FUNCTION_BLOCK "DIAGNOSTICA"
TITLE =Diagnostica
AUTHOR : D_T
VERSION : 0.1

BEGIN
NETWORK
TITLE =Mess.#001 - Emergenze non ripristinate

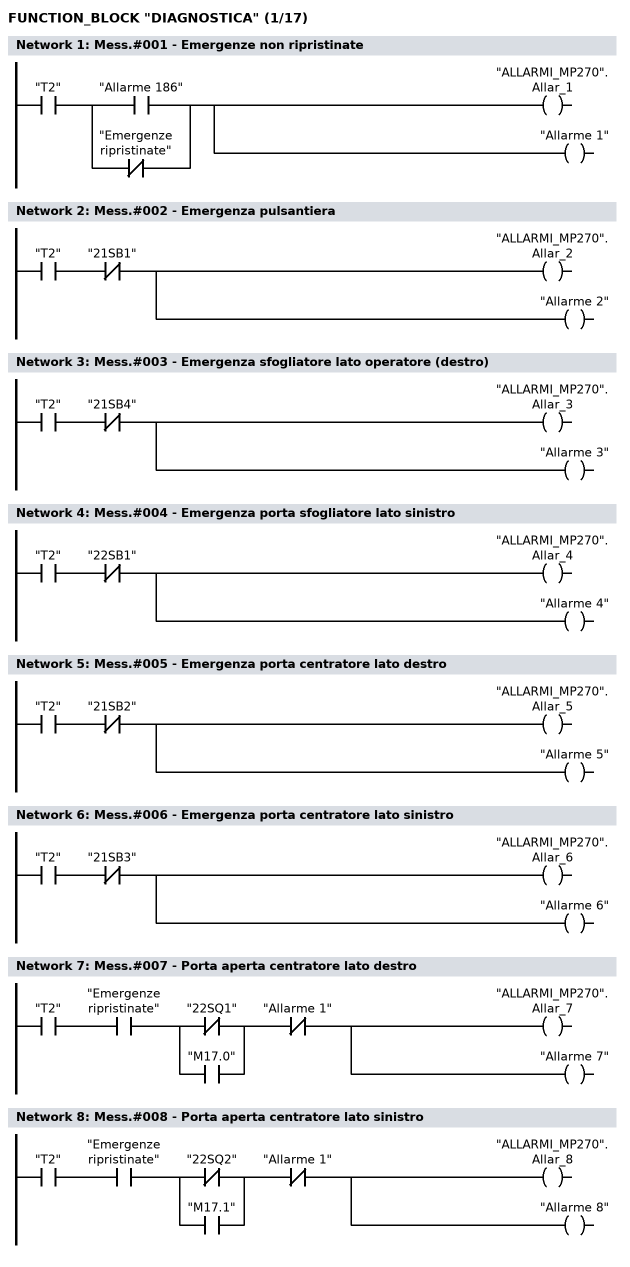
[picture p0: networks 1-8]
      U     "T2";
      U(    ;
      O     "Allarme 186";
      ON    "Emergenze ripristinate";
      )     ;
      =     "ALLARMI_MP270".Allar_1;
      =     "Allarme 1";
NETWORK
TITLE =Mess.#002 - Emergenza pulsantiera

      U     "T2";
      UN    "21SB1";
      =     "ALLARMI_MP270".Allar_2;
      =     "Allarme 2";
NETWORK
TITLE =Mess.#003 - Emergenza sfogliatore lato operatore (destro)

      U     "T2";
      UN    "21SB4";
      =     "ALLARMI_MP270".Allar_3;
      =     "Allarme 3";
NETWORK
TITLE =Mess.#004 - Emergenza porta sfogliatore lato sinistro

      U     "T2";
      UN    "22SB1";
      =     "ALLARMI_MP270".Allar_4;
      =     "Allarme 4";
NETWORK
TITLE =Mess.#005 - Emergenza porta centratore lato destro

      U     "T2";
      UN    "21SB2";
      =     "ALLARMI_MP270".Allar_5;
      =     "Allarme 5";
NETWORK
TITLE =Mess.#006 - Emergenza porta centratore lato sinistro

      U     "T2";
      UN    "21SB3";
      =     "ALLARMI_MP270".Allar_6;
      =     "Allarme 6";
NETWORK
TITLE =Mess.#007 - Porta aperta centratore lato destro

      U     "T2";
      U     "Emergenze ripristinate";
      U(    ;
      ON    "22SQ1";
      O     "M17.0";
      )     ;
      UN    "Allarme 1";
      =     "ALLARMI_MP270".Allar_7;
      =     "Allarme 7";
NETWORK
TITLE =Mess.#008 - Porta aperta centratore lato sinistro

      U     "T2";
      U     "Emergenze ripristinate";
      U(    ;
      ON    "22SQ2";
      O     "M17.1";
      )     ;
      UN    "Allarme 1";
      =     "ALLARMI_MP270".Allar_8;
      =     "Allarme 8";
NETWORK
TITLE =Mess.#009 - Magnetotermici 24 Volt drive

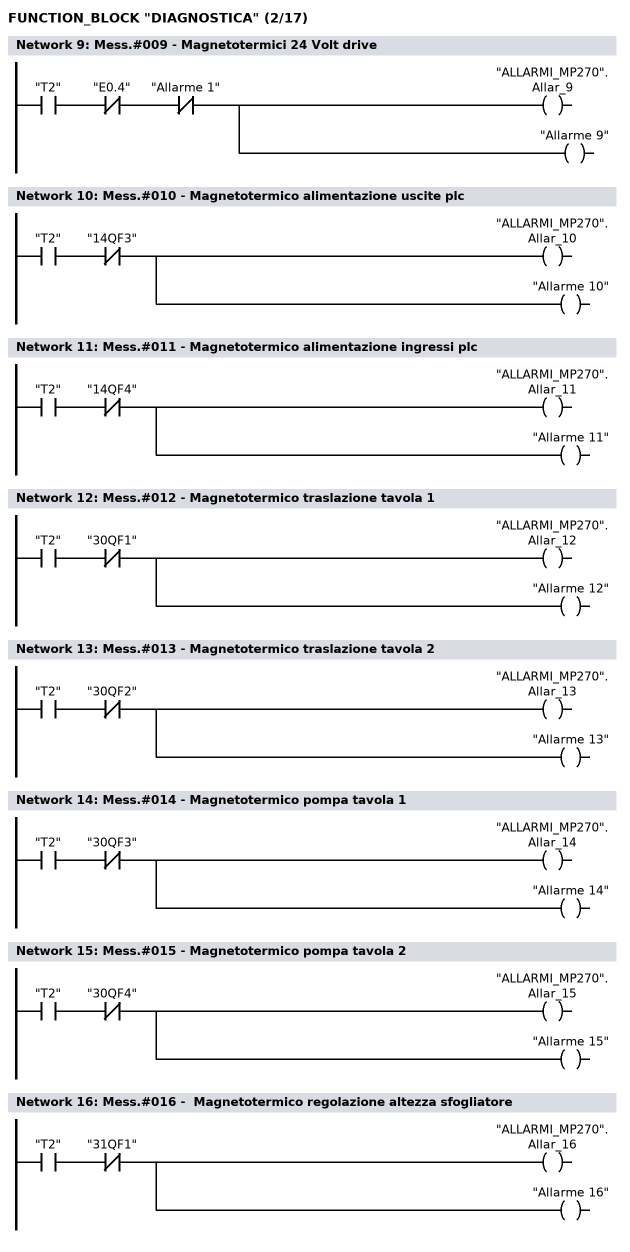
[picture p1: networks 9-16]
      U     "T2";
      UN    "E0.4";
      UN    "Allarme 1";
      =     "ALLARMI_MP270".Allar_9;
      =     "Allarme 9";
NETWORK
TITLE =Mess.#010 - Magnetotermico alimentazione uscite plc

      U     "T2";
      UN    "14QF3";
      =     "ALLARMI_MP270".Allar_10;
      =     "Allarme 10";
NETWORK
TITLE =Mess.#011 - Magnetotermico alimentazione ingressi plc

      U     "T2";
      UN    "14QF4";
      =     "ALLARMI_MP270".Allar_11;
      =     "Allarme 11";
NETWORK
TITLE =Mess.#012 - Magnetotermico traslazione tavola 1

      U     "T2";
      UN    "30QF1";
      =     "ALLARMI_MP270".Allar_12;
      =     "Allarme 12";
NETWORK
TITLE =Mess.#013 - Magnetotermico traslazione tavola 2

      U     "T2";
      UN    "30QF2";
      =     "ALLARMI_MP270".Allar_13;
      =     "Allarme 13";
NETWORK
TITLE =Mess.#014 - Magnetotermico pompa tavola 1

      U     "T2";
      UN    "30QF3";
      =     "ALLARMI_MP270".Allar_14;
      =     "Allarme 14";
NETWORK
TITLE =Mess.#015 - Magnetotermico pompa tavola 2

      U     "T2";
      UN    "30QF4";
      =     "ALLARMI_MP270".Allar_15;
      =     "Allarme 15";
NETWORK
TITLE =Mess.#016 -  Magnetotermico regolazione altezza sfogliatore

      U     "T2";
      UN    "31QF1";
      =     "ALLARMI_MP270".Allar_16;
      =     "Allarme 16";
NETWORK
TITLE =Mess.#017 - Magnetotermico regolazione altezza centratore

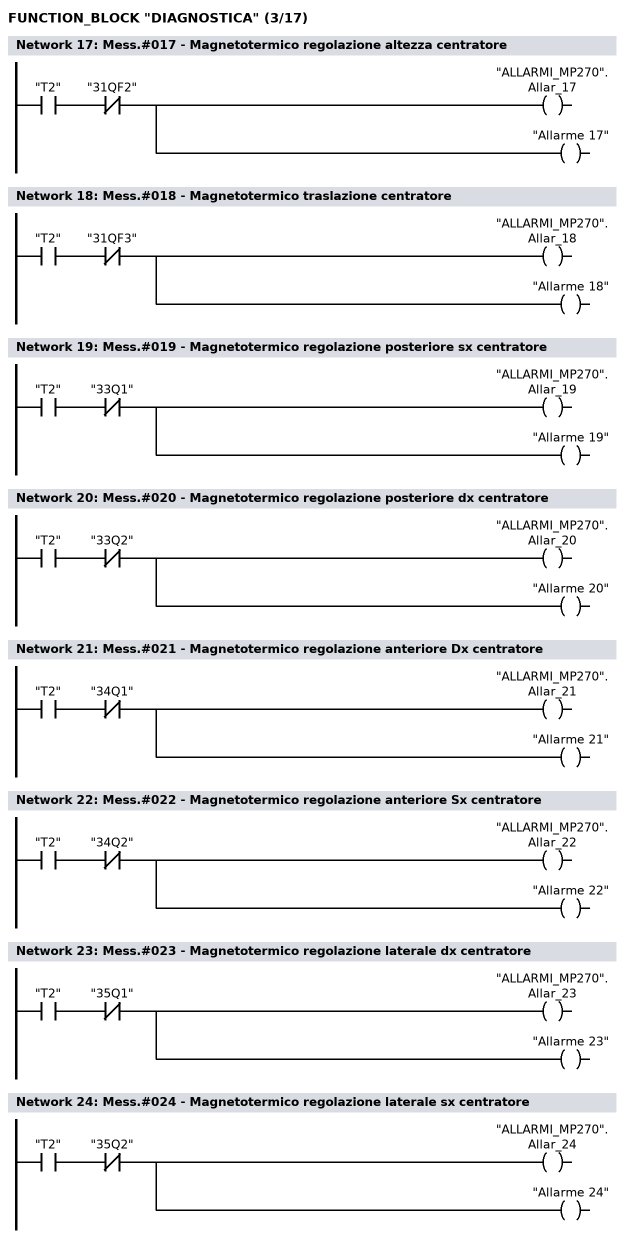
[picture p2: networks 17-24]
      U     "T2";
      UN    "31QF2";
      =     "ALLARMI_MP270".Allar_17;
      =     "Allarme 17";
NETWORK
TITLE =Mess.#018 - Magnetotermico traslazione centratore

      U     "T2";
      UN    "31QF3";
      =     "ALLARMI_MP270".Allar_18;
      =     "Allarme 18";
NETWORK
TITLE =Mess.#019 - Magnetotermico regolazione posteriore sx centratore

      U     "T2";
      UN    "33Q1";
      =     "ALLARMI_MP270".Allar_19;
      =     "Allarme 19";
NETWORK
TITLE =Mess.#020 - Magnetotermico regolazione posteriore dx centratore

      U     "T2";
      UN    "33Q2";
      =     "ALLARMI_MP270".Allar_20;
      =     "Allarme 20";
NETWORK
TITLE =Mess.#021 - Magnetotermico regolazione anteriore Dx centratore

      U     "T2";
      UN    "34Q1";
      =     "ALLARMI_MP270".Allar_21;
      =     "Allarme 21";
NETWORK
TITLE =Mess.#022 - Magnetotermico regolazione anteriore Sx centratore

      U     "T2";
      UN    "34Q2";
      =     "ALLARMI_MP270".Allar_22;
      =     "Allarme 22";
NETWORK
TITLE =Mess.#023 - Magnetotermico regolazione laterale dx centratore

      U     "T2";
      UN    "35Q1";
      =     "ALLARMI_MP270".Allar_23;
      =     "Allarme 23";
NETWORK
TITLE =Mess.#024 - Magnetotermico regolazione laterale sx centratore

      U     "T2";
      UN    "35Q2";
      =     "ALLARMI_MP270".Allar_24;
      =     "Allarme 24";
NETWORK
TITLE =Mess.#025 - Magnetotermico ventilatore armadio

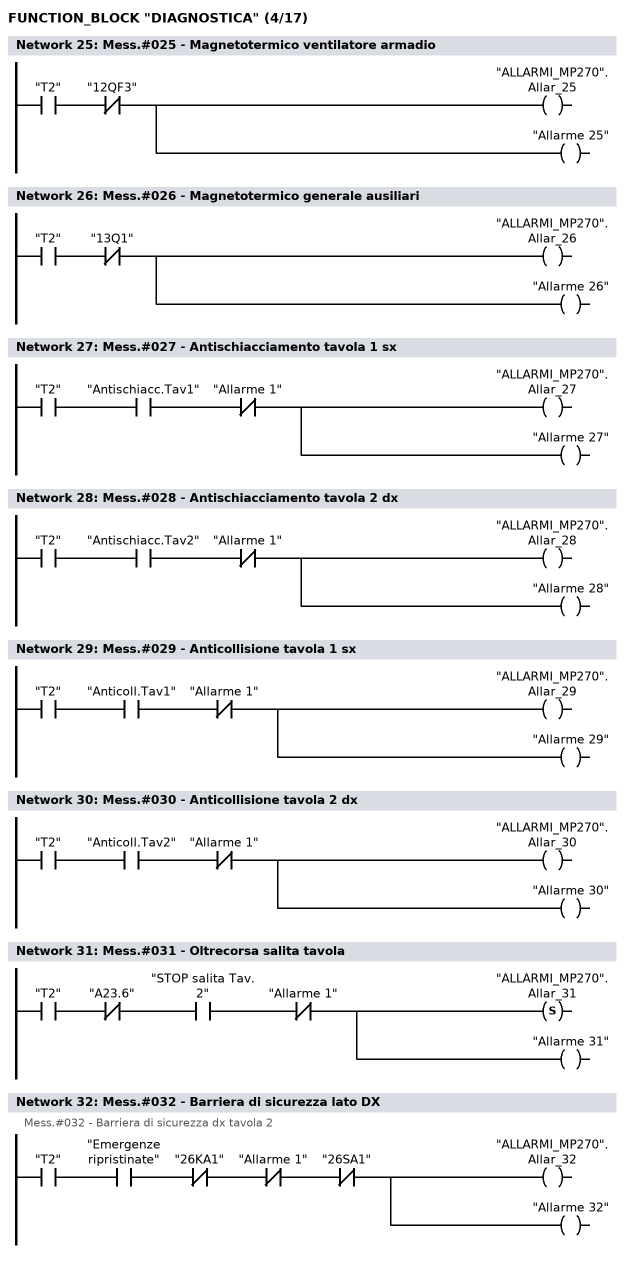
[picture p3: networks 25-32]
      U     "T2";
      UN    "12QF3";
      =     "ALLARMI_MP270".Allar_25;
      =     "Allarme 25";
NETWORK
TITLE =Mess.#026 - Magnetotermico generale ausiliari

      U     "T2";
      UN    "13Q1";
      =     "ALLARMI_MP270".Allar_26;
      =     "Allarme 26";
NETWORK
TITLE =Mess.#027 - Antischiacciamento tavola 1 sx

      U     "T2";
      U     "Antischiacc.Tav1";
      UN    "Allarme 1";
      =     "ALLARMI_MP270".Allar_27;
      =     "Allarme 27";
NETWORK
TITLE =Mess.#028 - Antischiacciamento tavola 2 dx

      U     "T2";
      U     "Antischiacc.Tav2";
      UN    "Allarme 1";
      =     "ALLARMI_MP270".Allar_28;
      =     "Allarme 28";
NETWORK
TITLE =Mess.#029 - Anticollisione tavola 1 sx

      U     "T2";
      U     "Anticoll.Tav1";
      UN    "Allarme 1";
      =     "ALLARMI_MP270".Allar_29;
      =     "Allarme 29";
NETWORK
TITLE =Mess.#030 - Anticollisione tavola 2 dx

      U     "T2";
      U     "Anticoll.Tav2";
      UN    "Allarme 1";
      =     "ALLARMI_MP270".Allar_30;
      =     "Allarme 30";
NETWORK
TITLE =Mess.#031 - Oltrecorsa salita tavola

      U     "T2";
      UN    "A23.6";
      U     "STOP salita Tav. 2";
      UN    "Allarme 1";
      S     "ALLARMI_MP270".Allar_31;
      =     "Allarme 31";
NETWORK
TITLE =Mess.#032 - Barriera di sicurezza lato DX
//Mess.#032 - Barriera di sicurezza dx tavola 2
      U     "T2";
      U     "Emergenze ripristinate";
      UN    "26KA1";
      UN    "Allarme 1";
      UN    "26SA1";
      =     "ALLARMI_MP270".Allar_32;
      =     "Allarme 32";
NETWORK
TITLE =Mess.#033 - Da AP&T: Segnale di start troppo lungo ad Abb

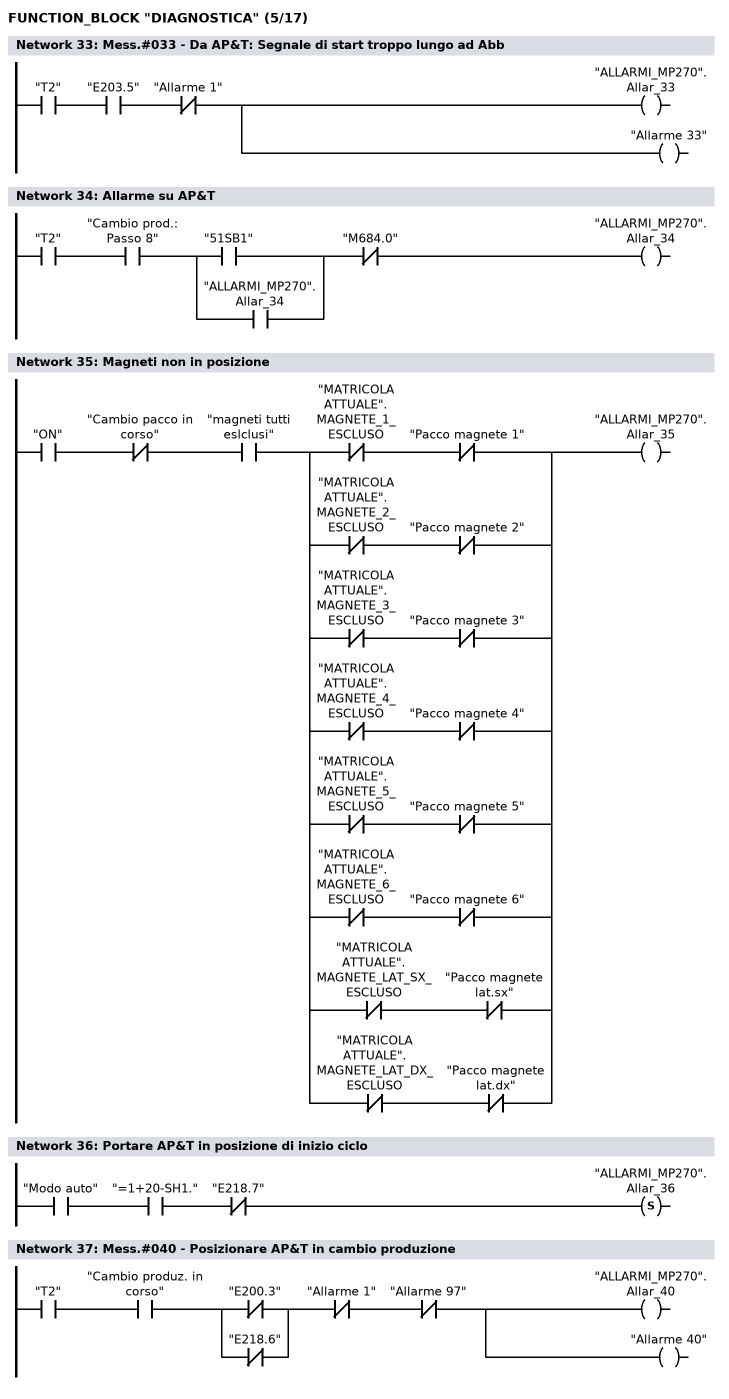
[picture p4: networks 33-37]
      U     "T2";
      U     "E203.5";
      UN    "Allarme 1";
      =     "ALLARMI_MP270".Allar_33;
      =     "Allarme 33";
NETWORK
TITLE =Allarme su AP&T

      U     "T2";
      U     "Cambio prod.: Passo 8";
      U(    ;
      O     "51SB1";
      O     "ALLARMI_MP270".Allar_34;
      )     ;
      UN    "M684.0";
      =     "ALLARMI_MP270".Allar_34;
NETWORK
TITLE =Magneti non in posizione

      U     "ON";
      UN    "Cambio pacco in corso";
      U     "magneti tutti eslclusi";
      U(    ;
      UN    "MATRICOLA ATTUALE".MAGNETE_1_ESCLUSO;
      UN    "Pacco magnete 1";
      O     ;
      UN    "MATRICOLA ATTUALE".MAGNETE_2_ESCLUSO;
      UN    "Pacco magnete 2";
      O     ;
      UN    "MATRICOLA ATTUALE".MAGNETE_3_ESCLUSO;
      UN    "Pacco magnete 3";
      O     ;
      UN    "MATRICOLA ATTUALE".MAGNETE_4_ESCLUSO;
      UN    "Pacco magnete 4";
      O     ;
      UN    "MATRICOLA ATTUALE".MAGNETE_5_ESCLUSO;
      UN    "Pacco magnete 5";
      O     ;
      UN    "MATRICOLA ATTUALE".MAGNETE_6_ESCLUSO;
      UN    "Pacco magnete 6";
      O     ;
      UN    "MATRICOLA ATTUALE".MAGNETE_LAT_SX_ESCLUSO;
      UN    "Pacco magnete lat.sx";
      O     ;
      UN    "MATRICOLA ATTUALE".MAGNETE_LAT_DX_ESCLUSO;
      UN    "Pacco magnete lat.dx";
      )     ;
      =     "ALLARMI_MP270".Allar_35;
NETWORK
TITLE =Portare AP&T in posizione di inizio ciclo

      U     "Modo auto";
      U     "=1+20-SH1.";
      UN    "E218.7";
      S     "ALLARMI_MP270".Allar_36;
NETWORK
TITLE =Mess.#040 - Posizionare AP&T in cambio produzione

      U     "T2";
      U     "Cambio produz. in corso";
      U(    ;
      ON    "E200.3";
      ON    "E218.6";
      )     ;
      UN    "Allarme 1";
      UN    "Allarme 97";
      =     "ALLARMI_MP270".Allar_40;
      =     "Allarme 40";
NETWORK
TITLE =Mess.#041 - Sicurezze antischiacc.e anticollisione escluse

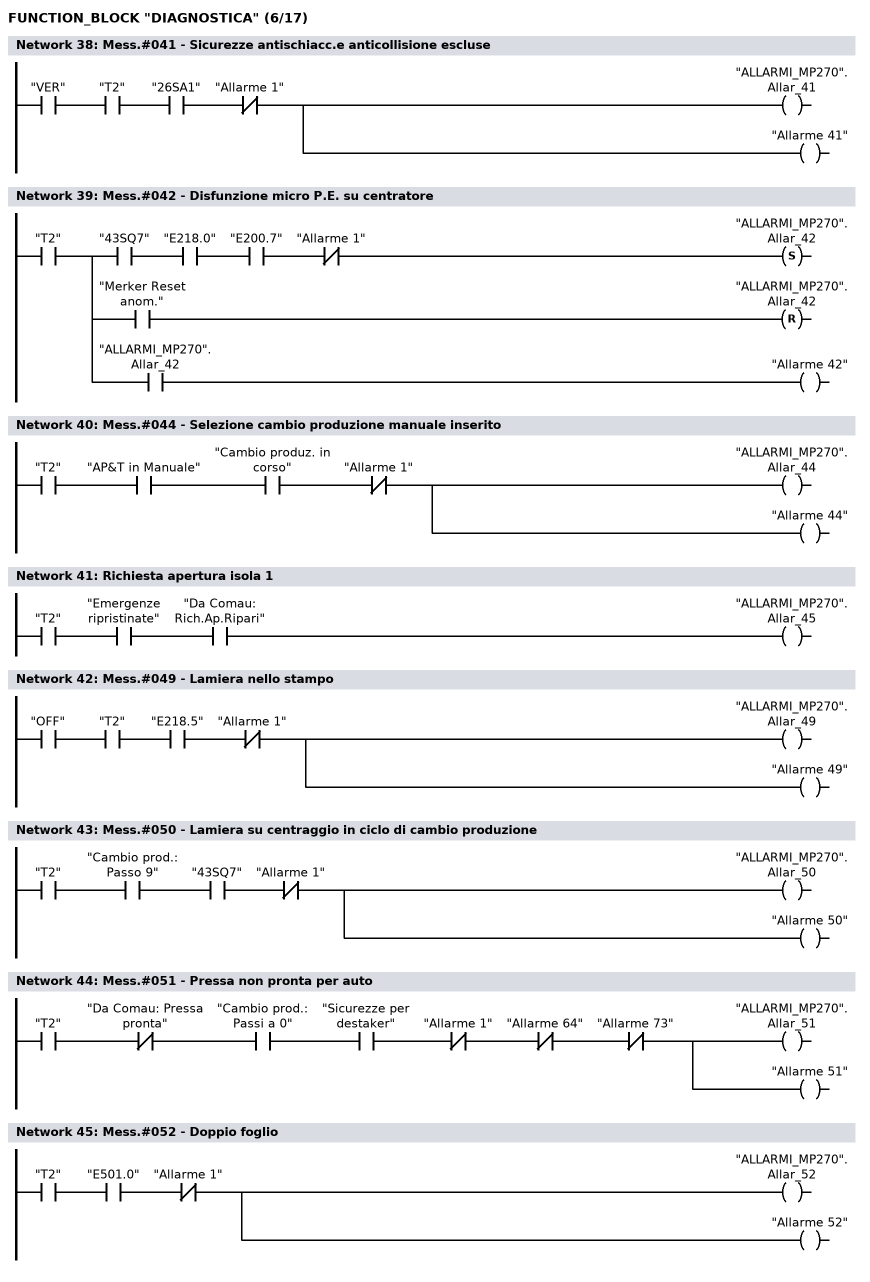
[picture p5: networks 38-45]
      U     "VER";
      U     "T2";
      U     "26SA1";
      UN    "Allarme 1";
      =     "ALLARMI_MP270".Allar_41;
      =     "Allarme 41";
NETWORK
TITLE =Mess.#042 - Disfunzione micro P.E. su centratore

      U     "T2";
      =     L      0.0;
      U     L      0.0;
      U     "43SQ7";
      U     "E218.0";
      U     "E200.7";
      UN    "Allarme 1";
      S     "ALLARMI_MP270".Allar_42;
      U     L      0.0;
      U     "Merker Reset anom.";
      R     "ALLARMI_MP270".Allar_42;
      U     L      0.0;
      U     "ALLARMI_MP270".Allar_42;
      =     "Allarme 42";
NETWORK
TITLE =Mess.#044 - Selezione cambio produzione manuale inserito

      U     "T2";
      U     "AP&T in Manuale";
      U     "Cambio produz. in corso";
      UN    "Allarme 1";
      =     "ALLARMI_MP270".Allar_44;
      =     "Allarme 44";
NETWORK
TITLE =Richiesta apertura isola 1

      U     "T2";
      U     "Emergenze ripristinate";
      U     "Da Comau: Rich.Ap.Ripari";
      =     "ALLARMI_MP270".Allar_45;
NETWORK
TITLE =Mess.#049 - Lamiera nello stampo

      U     "OFF";
      U     "T2";
      U     "E218.5";
      UN    "Allarme 1";
      =     "ALLARMI_MP270".Allar_49;
      =     "Allarme 49";
NETWORK
TITLE =Mess.#050 - Lamiera su centraggio in ciclo di cambio produzione

      U     "T2";
      U     "Cambio prod.: Passo 9";
      U     "43SQ7";
      UN    "Allarme 1";
      =     "ALLARMI_MP270".Allar_50;
      =     "Allarme 50";
NETWORK
TITLE =Mess.#051 - Pressa non pronta per auto

      U     "T2";
      UN    "Da Comau: Pressa pronta";
      U     "Cambio prod.: Passi a 0";
      U     "Sicurezze per destaker";
      UN    "Allarme 1";
      UN    "Allarme 64";
      UN    "Allarme 73";
      =     "ALLARMI_MP270".Allar_51;
      =     "Allarme 51";
NETWORK
TITLE =Mess.#052 - Doppio foglio

      U     "T2";
      U     "E501.0";
      UN    "Allarme 1";
      =     "ALLARMI_MP270".Allar_52;
      =     "Allarme 52";
NETWORK
TITLE =Mess.#053 - Robot non pronto per auto

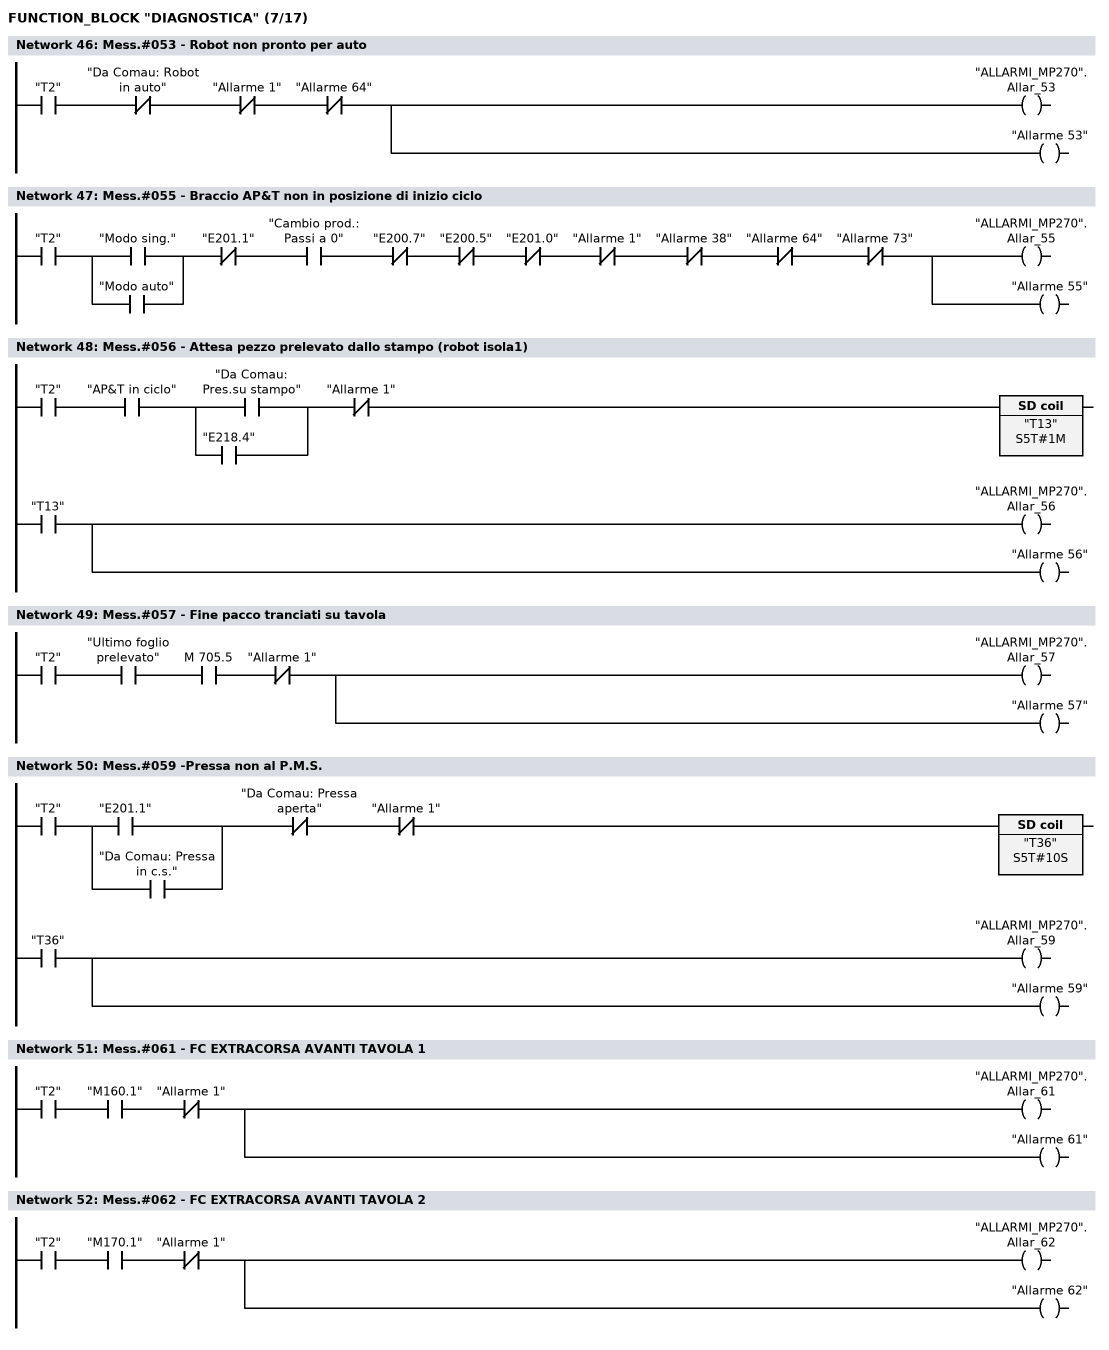
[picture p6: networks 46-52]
      U     "T2";
      UN    "Da Comau: Robot in auto";
      UN    "Allarme 1";
      UN    "Allarme 64";
      =     "ALLARMI_MP270".Allar_53;
      =     "Allarme 53";
NETWORK
TITLE =Mess.#055 - Braccio AP&T non in posizione di inizio ciclo

      U     "T2";
      U(    ;
      O     "Modo sing.";
      O     "Modo auto";
      )     ;
      UN    "E201.1";
      U     "Cambio prod.: Passi a 0";
      UN    "E200.7";
      UN    "E200.5";
      UN    "E201.0";
      UN    "Allarme 1";
      UN    "Allarme 38";
      UN    "Allarme 64";
      UN    "Allarme 73";
      =     "ALLARMI_MP270".Allar_55;
      =     "Allarme 55";
NETWORK
TITLE =Mess.#056 - Attesa pezzo prelevato dallo stampo (robot isola1)

      U     "T2";
      U     "AP&T  in ciclo";
      U(    ;
      O     "Da Comau: Pres.su stampo";
      O     "E218.4";
      )     ;
      UN    "Allarme 1";
      L     S5T#1M;
      SE    "T13";
      NOP   0;
      NOP   0;
      NOP   0;
      U     "T13";
      =     "ALLARMI_MP270".Allar_56;
      =     "Allarme 56";
NETWORK
TITLE =Mess.#057 - Fine pacco tranciati su tavola

      U     "T2";
      U     "Ultimo foglio prelevato";
      U     M    705.5;
      UN    "Allarme 1";
      =     "ALLARMI_MP270".Allar_57;
      =     "Allarme 57";
NETWORK
TITLE =Mess.#059 -Pressa non al P.M.S.

      U     "T2";
      U(    ;
      O     "E201.1";
      O     "Da Comau: Pressa in c.s.";
      )     ;
      UN    "Da Comau: Pressa aperta";
      UN    "Allarme 1";
      L     S5T#10S;
      SE    "T36";
      NOP   0;
      NOP   0;
      NOP   0;
      U     "T36";
      =     "ALLARMI_MP270".Allar_59;
      =     "Allarme 59";
NETWORK
TITLE =Mess.#061 - FC EXTRACORSA AVANTI TAVOLA 1

      U     "T2";
      U     "M160.1";
      UN    "Allarme 1";
      =     "ALLARMI_MP270".Allar_61;
      =     "Allarme 61";
NETWORK
TITLE =Mess.#062 - FC EXTRACORSA AVANTI TAVOLA 2

      U     "T2";
      U     "M170.1";
      UN    "Allarme 1";
      =     "ALLARMI_MP270".Allar_62;
      =     "Allarme 62";
NETWORK
TITLE =Mess.#063 -  Ciclo di ripresa per perdita consenso da robot
//da capire come farlo
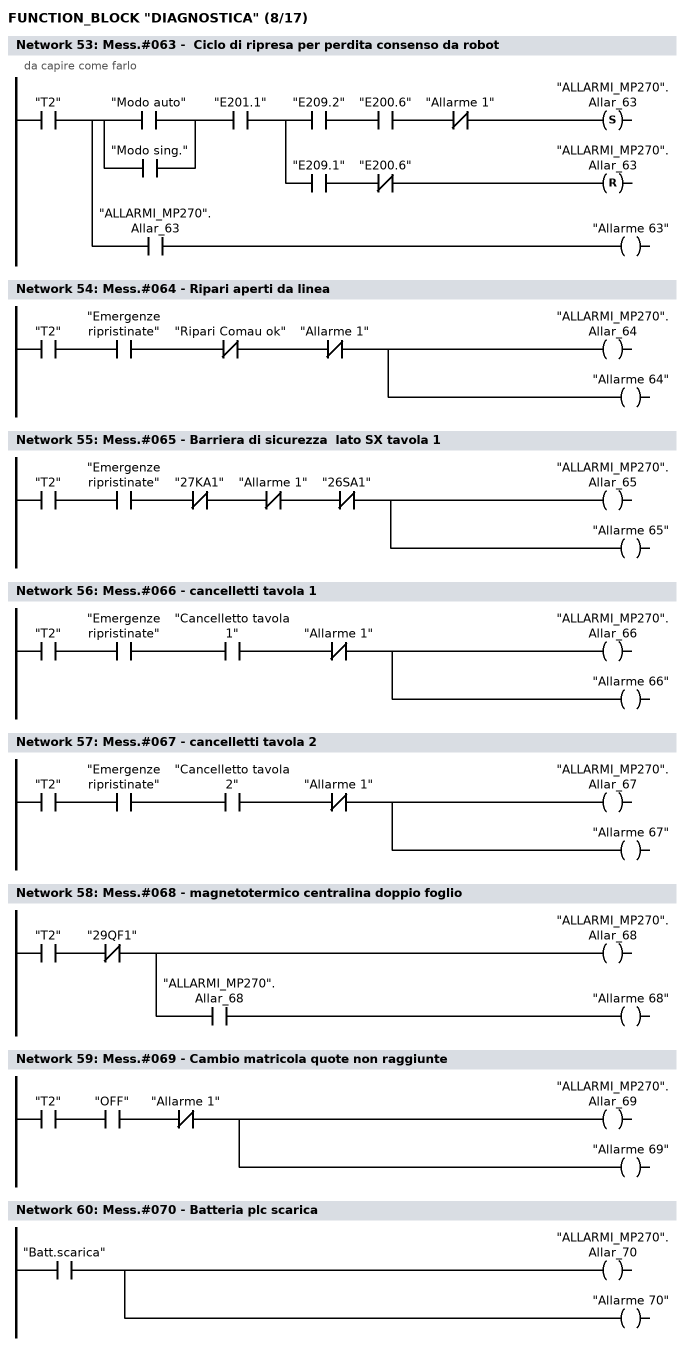
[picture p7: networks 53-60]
      U     "T2";
      =     L      0.0;
      U     L      0.0;
      U(    ;
      O     "Modo auto";
      O     "Modo sing.";
      )     ;
      U     "E201.1";
      =     L      0.1;
      U     L      0.1;
      U     "E209.2";
      U     "E200.6";
      UN    "Allarme 1";
      S     "ALLARMI_MP270".Allar_63;
      U     L      0.1;
      U     "E209.1";
      UN    "E200.6";
      R     "ALLARMI_MP270".Allar_63;
      U     L      0.0;
      U     "ALLARMI_MP270".Allar_63;
      =     "Allarme 63";
NETWORK
TITLE =Mess.#064 - Ripari aperti da linea

      U     "T2";
      U     "Emergenze ripristinate";
      UN    "Ripari Comau ok";
      UN    "Allarme 1";
      =     "ALLARMI_MP270".Allar_64;
      =     "Allarme 64";
NETWORK
TITLE =Mess.#065 - Barriera di sicurezza  lato SX tavola 1

      U     "T2";
      U     "Emergenze ripristinate";
      UN    "27KA1";
      UN    "Allarme 1";
      UN    "26SA1";
      =     "ALLARMI_MP270".Allar_65;
      =     "Allarme 65";
NETWORK
TITLE =Mess.#066 - cancelletti tavola 1

      U     "T2";
      U     "Emergenze ripristinate";
      U     "Cancelletto tavola 1";
      UN    "Allarme 1";
      =     "ALLARMI_MP270".Allar_66;
      =     "Allarme 66";
NETWORK
TITLE =Mess.#067 - cancelletti tavola 2

      U     "T2";
      U     "Emergenze ripristinate";
      U     "Cancelletto tavola 2";
      UN    "Allarme 1";
      =     "ALLARMI_MP270".Allar_67;
      =     "Allarme 67";
NETWORK
TITLE =Mess.#068 - magnetotermico centralina doppio foglio

      U     "T2";
      UN    "29QF1";
      =     L      0.0;
      U     L      0.0;
      BLD   102;
      =     "ALLARMI_MP270".Allar_68;
      U     L      0.0;
      U     "ALLARMI_MP270".Allar_68;
      =     "Allarme 68";
NETWORK
TITLE =Mess.#069 - Cambio matricola quote non raggiunte

      U     "T2";
      U     "OFF";
      UN    "Allarme 1";
      =     "ALLARMI_MP270".Allar_69;
      =     "Allarme 69";
NETWORK
TITLE =Mess.#070 - Batteria plc scarica

      U     "Batt.scarica";
      =     "ALLARMI_MP270".Allar_70;
      =     "Allarme 70";
NETWORK
TITLE =Mess.#071 - Tavola 1 non abbassata

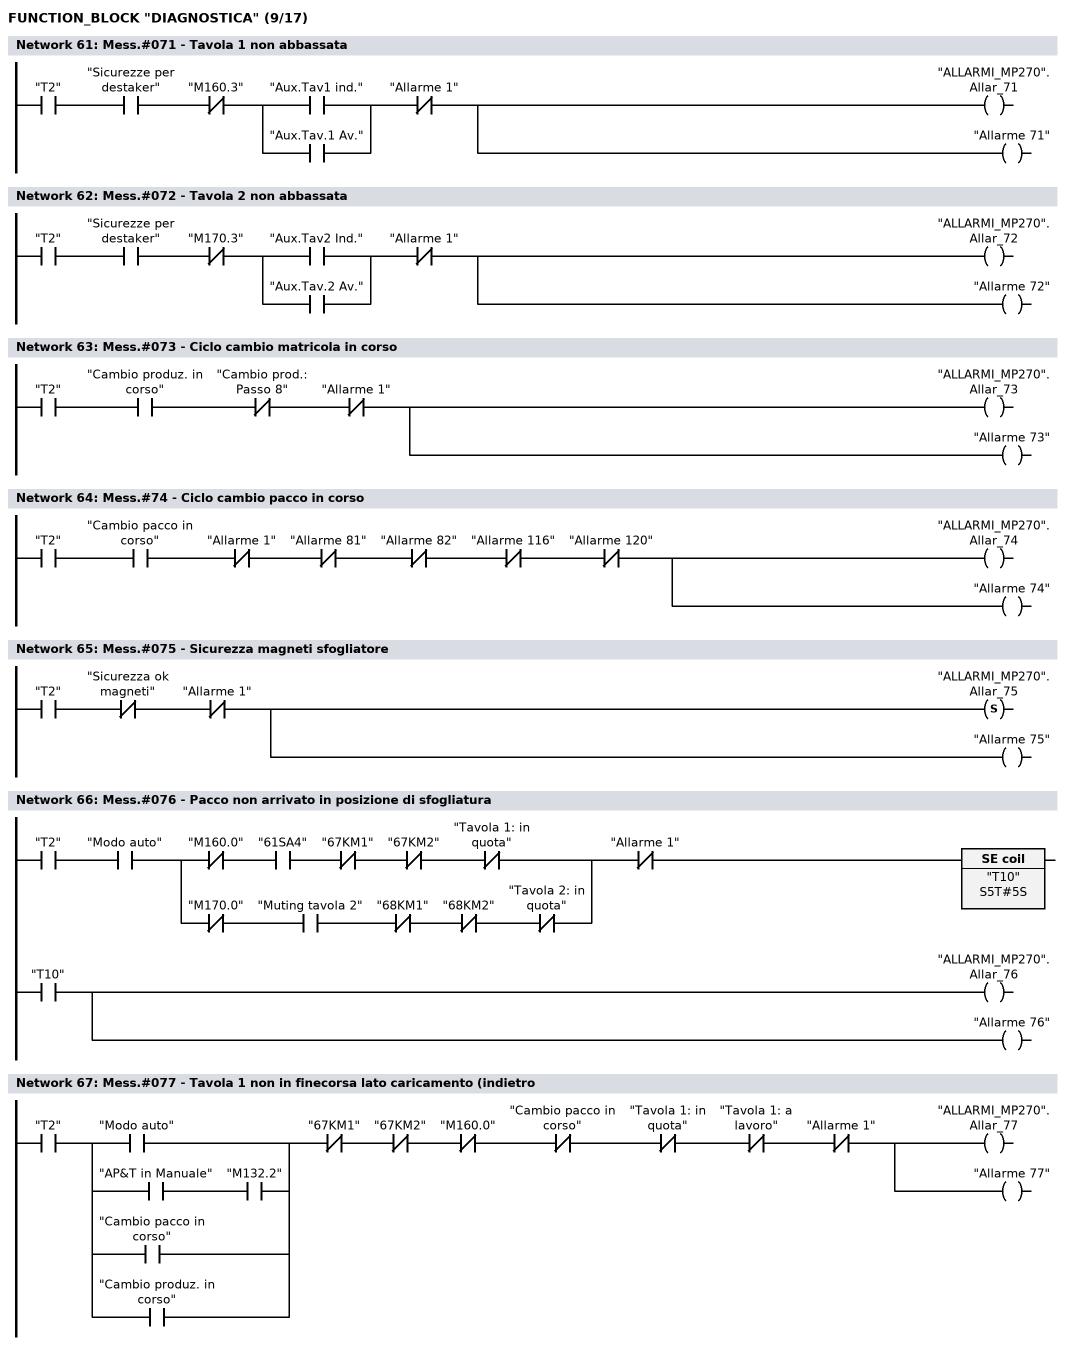
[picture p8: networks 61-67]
      U     "T2";
      U     "Sicurezze per destaker";
      UN    "M160.3";
      U(    ;
      O     "Aux.Tav1 ind.";
      O     "Aux.Tav.1 Av.";
      )     ;
      UN    "Allarme 1";
      =     "ALLARMI_MP270".Allar_71;
      =     "Allarme 71";
NETWORK
TITLE =Mess.#072 - Tavola 2 non abbassata

      U     "T2";
      U     "Sicurezze per destaker";
      UN    "M170.3";
      U(    ;
      O     "Aux.Tav2 Ind.";
      O     "Aux.Tav.2 Av.";
      )     ;
      UN    "Allarme 1";
      =     "ALLARMI_MP270".Allar_72;
      =     "Allarme 72";
NETWORK
TITLE =Mess.#073 - Ciclo cambio matricola in corso

      U     "T2";
      U     "Cambio produz. in corso";
      UN    "Cambio prod.: Passo 8";
      UN    "Allarme 1";
      =     "ALLARMI_MP270".Allar_73;
      =     "Allarme 73";
NETWORK
TITLE =Mess.#74 - Ciclo cambio pacco in corso

      U     "T2";
      U     "Cambio pacco in corso";
      UN    "Allarme 1";
      UN    "Allarme 81";
      UN    "Allarme 82";
      UN    "Allarme 116";
      UN    "Allarme 120";
      =     "ALLARMI_MP270".Allar_74;
      =     "Allarme 74";
NETWORK
TITLE =Mess.#075 - Sicurezza magneti sfogliatore

      U     "T2";
      UN    "Sicurezza ok magneti";
      UN    "Allarme 1";
      S     "ALLARMI_MP270".Allar_75;
      =     "Allarme 75";
NETWORK
TITLE =Mess.#076 - Pacco non arrivato in posizione di sfogliatura

      U     "T2";
      U     "Modo auto";
      U(    ;
      UN    "M160.0";
      U     "61SA4";
      UN    "67KM1";
      UN    "67KM2";
      UN    "Tavola 1: in quota";
      O     ;
      UN    "M170.0";
      U     "Muting tavola 2";
      UN    "68KM1";
      UN    "68KM2";
      UN    "Tavola 2: in quota";
      )     ;
      UN    "Allarme 1";
      L     S5T#5S;
      SV    "T10";
      NOP   0;
      NOP   0;
      NOP   0;
      U     "T10";
      =     "ALLARMI_MP270".Allar_76;
      =     "Allarme 76";
NETWORK
TITLE =Mess.#077 - Tavola 1 non in finecorsa lato caricamento (indietro

      U     "T2";
      U(    ;
      O     "Modo auto";
      O     ;
      U     "AP&T in Manuale";
      U     "M132.2";
      O     "Cambio pacco in corso";
      O     "Cambio produz. in corso";
      )     ;
      UN    "67KM1";
      UN    "67KM2";
      UN    "M160.0";
      UN    "Cambio pacco in corso";
      UN    "Tavola 1: in quota";
      UN    "Tavola 1: a  lavoro";
      UN    "Allarme 1";
      =     "ALLARMI_MP270".Allar_77;
      =     "Allarme 77";
NETWORK
TITLE =Mess.#078 - Tavola 2 non in finecorsa lato caricamento (indietro

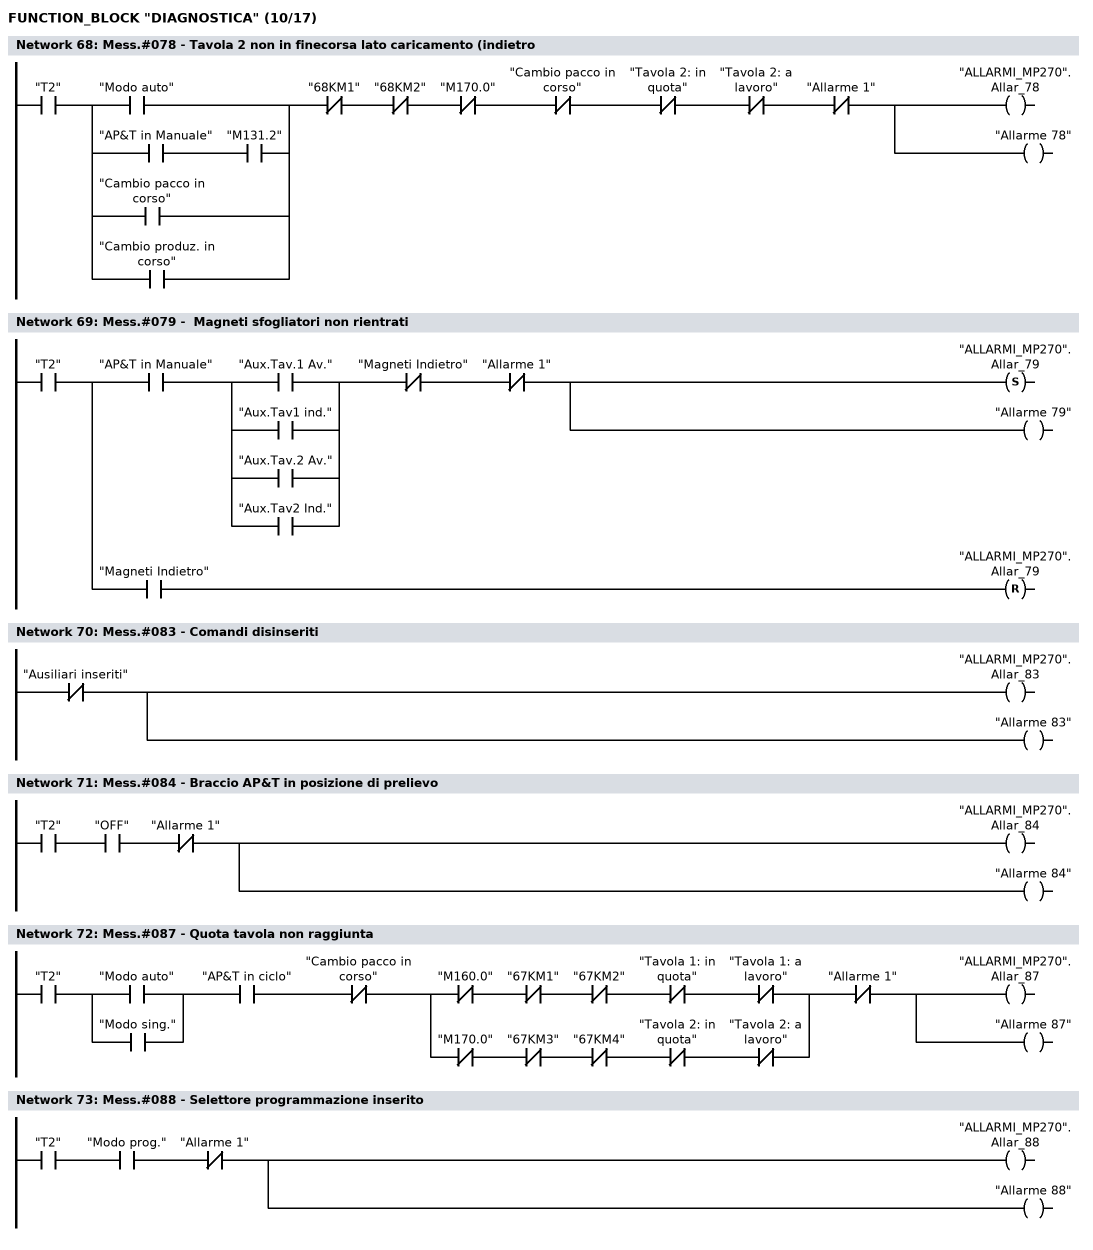
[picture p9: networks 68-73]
      U     "T2";
      U(    ;
      O     "Modo auto";
      O     ;
      U     "AP&T in Manuale";
      U     "M131.2";
      O     "Cambio pacco in corso";
      O     "Cambio produz. in corso";
      )     ;
      UN    "68KM1";
      UN    "68KM2";
      UN    "M170.0";
      UN    "Cambio pacco in corso";
      UN    "Tavola 2: in quota";
      UN    "Tavola 2: a  lavoro";
      UN    "Allarme 1";
      =     "ALLARMI_MP270".Allar_78;
      =     "Allarme 78";
NETWORK
TITLE =Mess.#079 -  Magneti sfogliatori non rientrati

      U     "T2";
      =     L      0.0;
      U     L      0.0;
      U     "AP&T in Manuale";
      U(    ;
      O     "Aux.Tav.1 Av.";
      O     "Aux.Tav1 ind.";
      O     "Aux.Tav.2 Av.";
      O     "Aux.Tav2 Ind.";
      )     ;
      UN    "Magneti Indietro";
      UN    "Allarme 1";
      S     "ALLARMI_MP270".Allar_79;
      =     "Allarme 79";
      U     L      0.0;
      U     "Magneti Indietro";
      R     "ALLARMI_MP270".Allar_79;
NETWORK
TITLE =Mess.#083 - Comandi disinseriti

      UN    "Ausiliari inseriti";
      =     "ALLARMI_MP270".Allar_83;
      =     "Allarme 83";
NETWORK
TITLE =Mess.#084 - Braccio AP&T in posizione di prelievo

      U     "T2";
      U     "OFF";
      UN    "Allarme 1";
      =     "ALLARMI_MP270".Allar_84;
      =     "Allarme 84";
NETWORK
TITLE =Mess.#087 - Quota tavola non raggiunta

      U     "T2";
      U(    ;
      O     "Modo auto";
      O     "Modo sing.";
      )     ;
      U     "AP&T  in ciclo";
      UN    "Cambio pacco in corso";
      U(    ;
      UN    "M160.0";
      UN    "67KM1";
      UN    "67KM2";
      UN    "Tavola 1: in quota";
      UN    "Tavola 1: a  lavoro";
      O     ;
      UN    "M170.0";
      UN    "67KM3";
      UN    "67KM4";
      UN    "Tavola 2: in quota";
      UN    "Tavola 2: a  lavoro";
      )     ;
      UN    "Allarme 1";
      =     "ALLARMI_MP270".Allar_87;
      =     "Allarme 87";
NETWORK
TITLE =Mess.#088 - Selettore programmazione inserito

      U     "T2";
      U     "Modo prog.";
      UN    "Allarme 1";
      =     "ALLARMI_MP270".Allar_88;
      =     "Allarme 88";
NETWORK
TITLE =Mess.#089 - Contemporaneita' fc  traslazione tavola 1

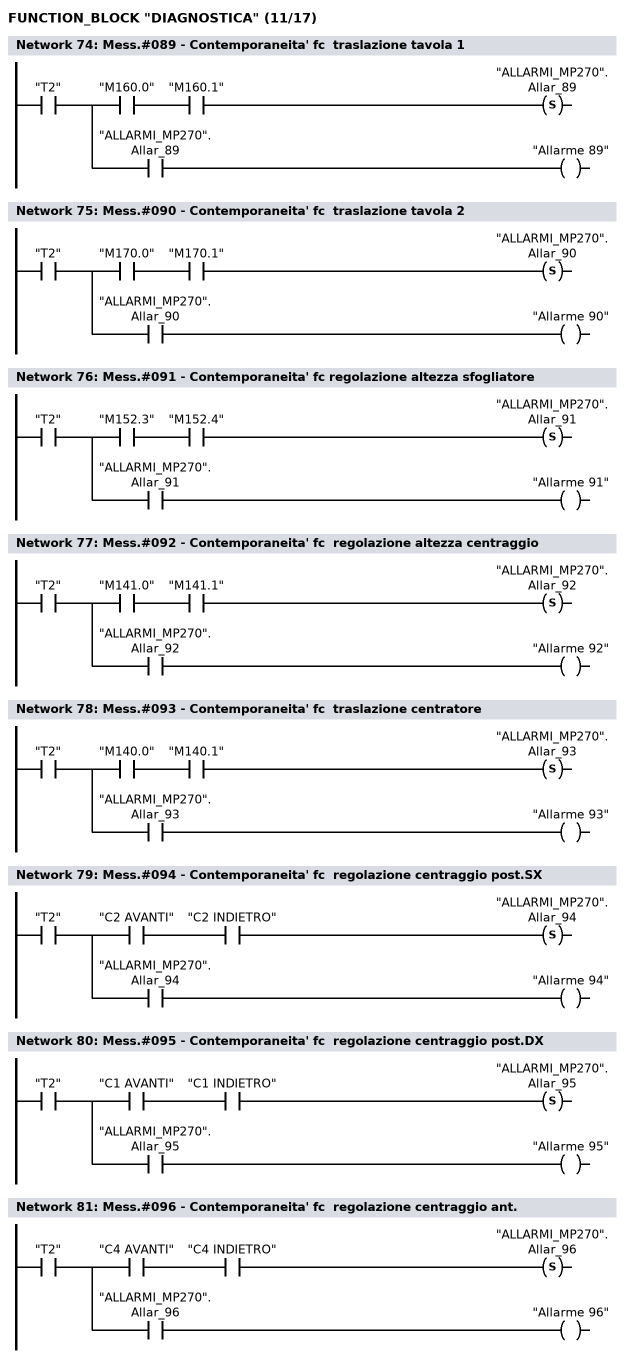
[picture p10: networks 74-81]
      U     "T2";
      =     L      0.0;
      U     L      0.0;
      U     "M160.0";
      U     "M160.1";
      S     "ALLARMI_MP270".Allar_89;
      U     L      0.0;
      U     "ALLARMI_MP270".Allar_89;
      =     "Allarme 89";
NETWORK
TITLE =Mess.#090 - Contemporaneita' fc  traslazione tavola 2

      U     "T2";
      =     L      0.0;
      U     L      0.0;
      U     "M170.0";
      U     "M170.1";
      S     "ALLARMI_MP270".Allar_90;
      U     L      0.0;
      U     "ALLARMI_MP270".Allar_90;
      =     "Allarme 90";
NETWORK
TITLE =Mess.#091 - Contemporaneita' fc regolazione altezza sfogliatore

      U     "T2";
      =     L      0.0;
      U     L      0.0;
      U     "M152.3";
      U     "M152.4";
      S     "ALLARMI_MP270".Allar_91;
      U     L      0.0;
      U     "ALLARMI_MP270".Allar_91;
      =     "Allarme 91";
NETWORK
TITLE =Mess.#092 - Contemporaneita' fc  regolazione altezza centraggio

      U     "T2";
      =     L      0.0;
      U     L      0.0;
      U     "M141.0";
      U     "M141.1";
      S     "ALLARMI_MP270".Allar_92;
      U     L      0.0;
      U     "ALLARMI_MP270".Allar_92;
      =     "Allarme 92";
NETWORK
TITLE =Mess.#093 - Contemporaneita' fc  traslazione centratore

      U     "T2";
      =     L      0.0;
      U     L      0.0;
      U     "M140.0";
      U     "M140.1";
      S     "ALLARMI_MP270".Allar_93;
      U     L      0.0;
      U     "ALLARMI_MP270".Allar_93;
      =     "Allarme 93";
NETWORK
TITLE =Mess.#094 - Contemporaneita' fc  regolazione centraggio post.SX

      U     "T2";
      =     L      0.0;
      U     L      0.0;
      U     "C2 AVANTI";
      U     "C2 INDIETRO";
      S     "ALLARMI_MP270".Allar_94;
      U     L      0.0;
      U     "ALLARMI_MP270".Allar_94;
      =     "Allarme 94";
NETWORK
TITLE =Mess.#095 - Contemporaneita' fc  regolazione centraggio post.DX

      U     "T2";
      =     L      0.0;
      U     L      0.0;
      U     "C1 AVANTI";
      U     "C1 INDIETRO";
      S     "ALLARMI_MP270".Allar_95;
      U     L      0.0;
      U     "ALLARMI_MP270".Allar_95;
      =     "Allarme 95";
NETWORK
TITLE =Mess.#096 - Contemporaneita' fc  regolazione centraggio ant.

      U     "T2";
      =     L      0.0;
      U     L      0.0;
      U     "C4 AVANTI";
      U     "C4 INDIETRO";
      S     "ALLARMI_MP270".Allar_96;
      U     L      0.0;
      U     "ALLARMI_MP270".Allar_96;
      =     "Allarme 96";
NETWORK
TITLE =Mess.#097 -Selezione cambio produzione in automatico

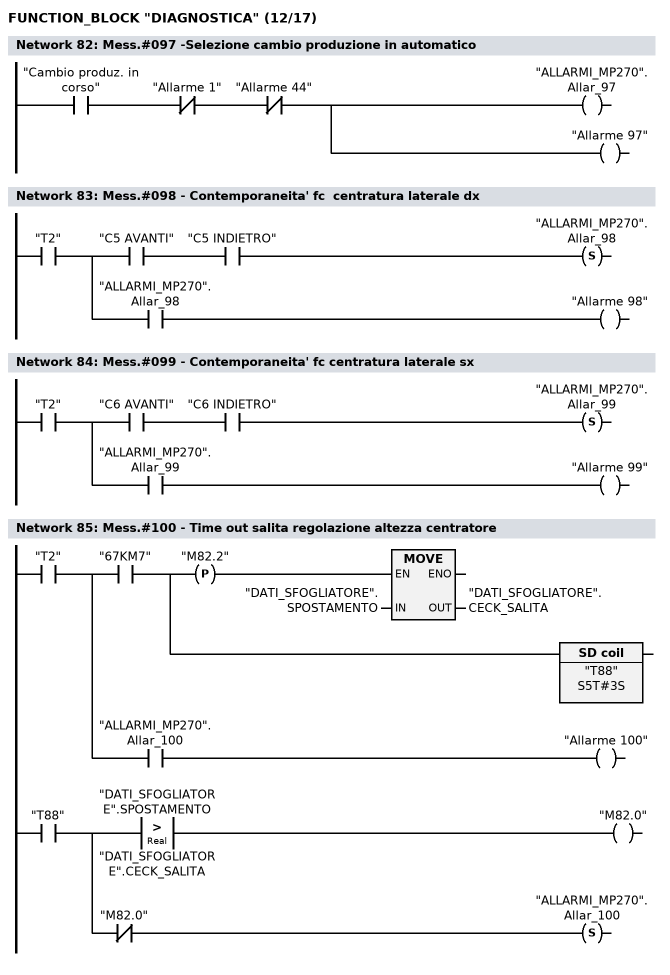
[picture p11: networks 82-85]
      U     "Cambio produz. in corso";
      UN    "Allarme 1";
      UN    "Allarme 44";
      =     "ALLARMI_MP270".Allar_97;
      =     "Allarme 97";
NETWORK
TITLE =Mess.#098 - Contemporaneita' fc  centratura laterale dx

      U     "T2";
      =     L      0.0;
      U     L      0.0;
      U     "C5 AVANTI";
      U     "C5 INDIETRO";
      S     "ALLARMI_MP270".Allar_98;
      U     L      0.0;
      U     "ALLARMI_MP270".Allar_98;
      =     "Allarme 98";
NETWORK
TITLE =Mess.#099 - Contemporaneita' fc centratura laterale sx

      U     "T2";
      =     L      0.0;
      U     L      0.0;
      U     "C6 AVANTI";
      U     "C6 INDIETRO";
      S     "ALLARMI_MP270".Allar_99;
      U     L      0.0;
      U     "ALLARMI_MP270".Allar_99;
      =     "Allarme 99";
NETWORK
TITLE =Mess.#100 - Time out salita regolazione altezza centratore

      U     "T2";
      =     L      0.0;
      U     L      0.0;
      U     "67KM7";
      =     L      0.1;
      U     L      0.1;
      FP    "M82.2";
      SPBNB _001;
      L     "DATI_SFOGLIATORE".SPOSTAMENTO;
      T     "DATI_SFOGLIATORE".CECK_SALITA;
_001: NOP   0;
      U     L      0.1;
      L     S5T#3S;
      SE    "T88";
      NOP   0;
      NOP   0;
      NOP   0;
      U     "T88";
      =     L      0.2;
      U     L      0.2;
      U(    ;
      L     "DATI_SFOGLIATORE".SPOSTAMENTO;
      L     "DATI_SFOGLIATORE".CECK_SALITA;
      >R    ;
      )     ;
      =     "M82.0";
      U     L      0.2;
      UN    "M82.0";
      S     "ALLARMI_MP270".Allar_100;
      U     L      0.0;
      U     "ALLARMI_MP270".Allar_100;
      =     "Allarme 100";
NETWORK
TITLE =Mess.#101 - Time out discesa regolazione altezza centratore

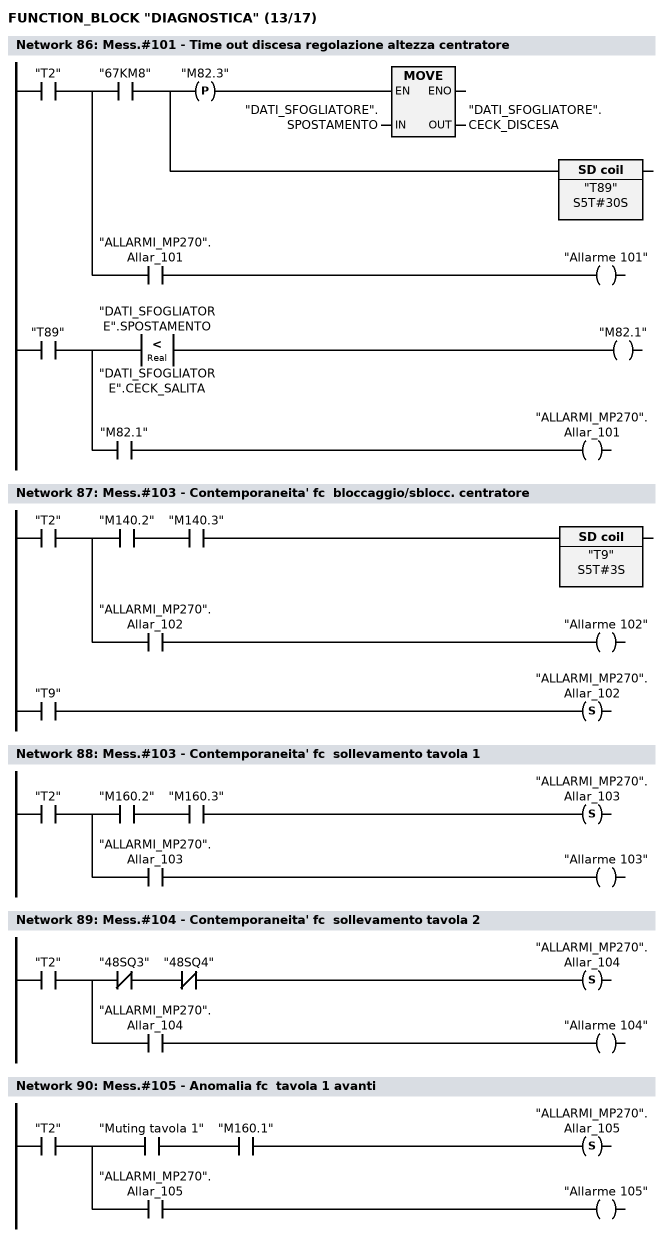
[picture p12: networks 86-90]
      U     "T2";
      =     L      0.0;
      U     L      0.0;
      U     "67KM8";
      =     L      0.1;
      U     L      0.1;
      FP    "M82.3";
      SPBNB _002;
      L     "DATI_SFOGLIATORE".SPOSTAMENTO;
      T     "DATI_SFOGLIATORE".CECK_DISCESA;
_002: NOP   0;
      U     L      0.1;
      L     S5T#30S;
      SE    "T89";
      NOP   0;
      NOP   0;
      NOP   0;
      U     "T89";
      =     L      0.2;
      U     L      0.2;
      U(    ;
      L     "DATI_SFOGLIATORE".SPOSTAMENTO;
      L     "DATI_SFOGLIATORE".CECK_SALITA;
      <R    ;
      )     ;
      =     "M82.1";
      U     L      0.2;
      U     "M82.1";
      =     "ALLARMI_MP270".Allar_101;
      U     L      0.0;
      U     "ALLARMI_MP270".Allar_101;
      =     "Allarme 101";
NETWORK
TITLE =Mess.#103 - Contemporaneita' fc  bloccaggio/sblocc. centratore

      U     "T2";
      =     L      0.0;
      U     L      0.0;
      U     "M140.2";
      U     "M140.3";
      L     S5T#3S;
      SE    "T9";
      NOP   0;
      NOP   0;
      NOP   0;
      U     "T9";
      S     "ALLARMI_MP270".Allar_102;
      U     L      0.0;
      U     "ALLARMI_MP270".Allar_102;
      =     "Allarme 102";
NETWORK
TITLE =Mess.#103 - Contemporaneita' fc  sollevamento tavola 1

      U     "T2";
      =     L      0.0;
      U     L      0.0;
      U     "M160.2";
      U     "M160.3";
      S     "ALLARMI_MP270".Allar_103;
      U     L      0.0;
      U     "ALLARMI_MP270".Allar_103;
      =     "Allarme 103";
NETWORK
TITLE =Mess.#104 - Contemporaneita' fc  sollevamento tavola 2

      U     "T2";
      =     L      0.0;
      U     L      0.0;
      UN    "48SQ3";
      UN    "48SQ4";
      S     "ALLARMI_MP270".Allar_104;
      U     L      0.0;
      U     "ALLARMI_MP270".Allar_104;
      =     "Allarme 104";
NETWORK
TITLE =Mess.#105 - Anomalia fc  tavola 1 avanti

      U     "T2";
      =     L      0.0;
      U     L      0.0;
      U     "Muting tavola 1";
      U     "M160.1";
      S     "ALLARMI_MP270".Allar_105;
      U     L      0.0;
      U     "ALLARMI_MP270".Allar_105;
      =     "Allarme 105";
NETWORK
TITLE =Mess.#106 - Anomalia fc  tavola 1 indietro

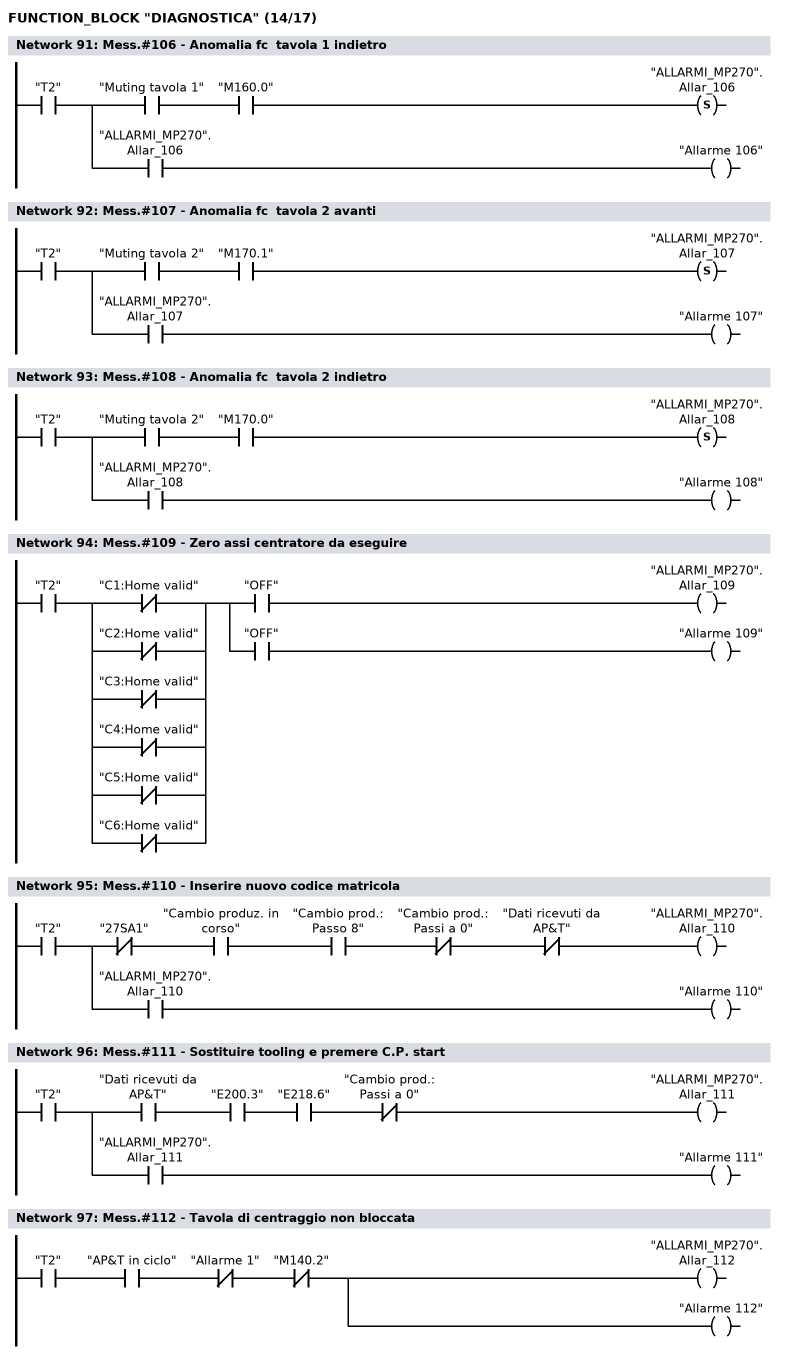
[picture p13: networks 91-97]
      U     "T2";
      =     L      0.0;
      U     L      0.0;
      U     "Muting tavola 1";
      U     "M160.0";
      S     "ALLARMI_MP270".Allar_106;
      U     L      0.0;
      U     "ALLARMI_MP270".Allar_106;
      =     "Allarme 106";
NETWORK
TITLE =Mess.#107 - Anomalia fc  tavola 2 avanti

      U     "T2";
      =     L      0.0;
      U     L      0.0;
      U     "Muting tavola 2";
      U     "M170.1";
      S     "ALLARMI_MP270".Allar_107;
      U     L      0.0;
      U     "ALLARMI_MP270".Allar_107;
      =     "Allarme 107";
NETWORK
TITLE =Mess.#108 - Anomalia fc  tavola 2 indietro

      U     "T2";
      =     L      0.0;
      U     L      0.0;
      U     "Muting tavola 2";
      U     "M170.0";
      S     "ALLARMI_MP270".Allar_108;
      U     L      0.0;
      U     "ALLARMI_MP270".Allar_108;
      =     "Allarme 108";
NETWORK
TITLE =Mess.#109 - Zero assi centratore da eseguire

      U     "T2";
      U(    ;
      ON    "C1:Home valid";
      ON    "C2:Home valid";
      ON    "C3:Home valid";
      ON    "C4:Home valid";
      ON    "C5:Home valid";
      ON    "C6:Home valid";
      )     ;
      =     L      0.0;
      U     L      0.0;
      U     "OFF";
      =     "ALLARMI_MP270".Allar_109;
      U     L      0.0;
      U     "OFF";
      =     "Allarme 109";
NETWORK
TITLE =Mess.#110 - Inserire nuovo codice matricola

      U     "T2";
      =     L      0.0;
      U     L      0.0;
      UN    "27SA1";
      U     "Cambio produz. in corso";
      U     "Cambio prod.: Passo 8";
      UN    "Cambio prod.: Passi a 0";
      UN    "Dati ricevuti da AP&T";
      =     "ALLARMI_MP270".Allar_110;
      U     L      0.0;
      U     "ALLARMI_MP270".Allar_110;
      =     "Allarme 110";
NETWORK
TITLE =Mess.#111 - Sostituire tooling e premere C.P. start

      U     "T2";
      =     L      0.0;
      U     L      0.0;
      U     "Dati ricevuti da AP&T";
      U     "E200.3";
      U     "E218.6";
      UN    "Cambio prod.: Passi a 0";
      =     "ALLARMI_MP270".Allar_111;
      U     L      0.0;
      U     "ALLARMI_MP270".Allar_111;
      =     "Allarme 111";
NETWORK
TITLE =Mess.#112 - Tavola di centraggio non bloccata

      U     "T2";
      U     "AP&T  in ciclo";
      UN    "Allarme 1";
      UN    "M140.2";
      =     "ALLARMI_MP270".Allar_112;
      =     "Allarme 112";
NETWORK
TITLE =Mess.#113 - Motori AP&T non inseriti

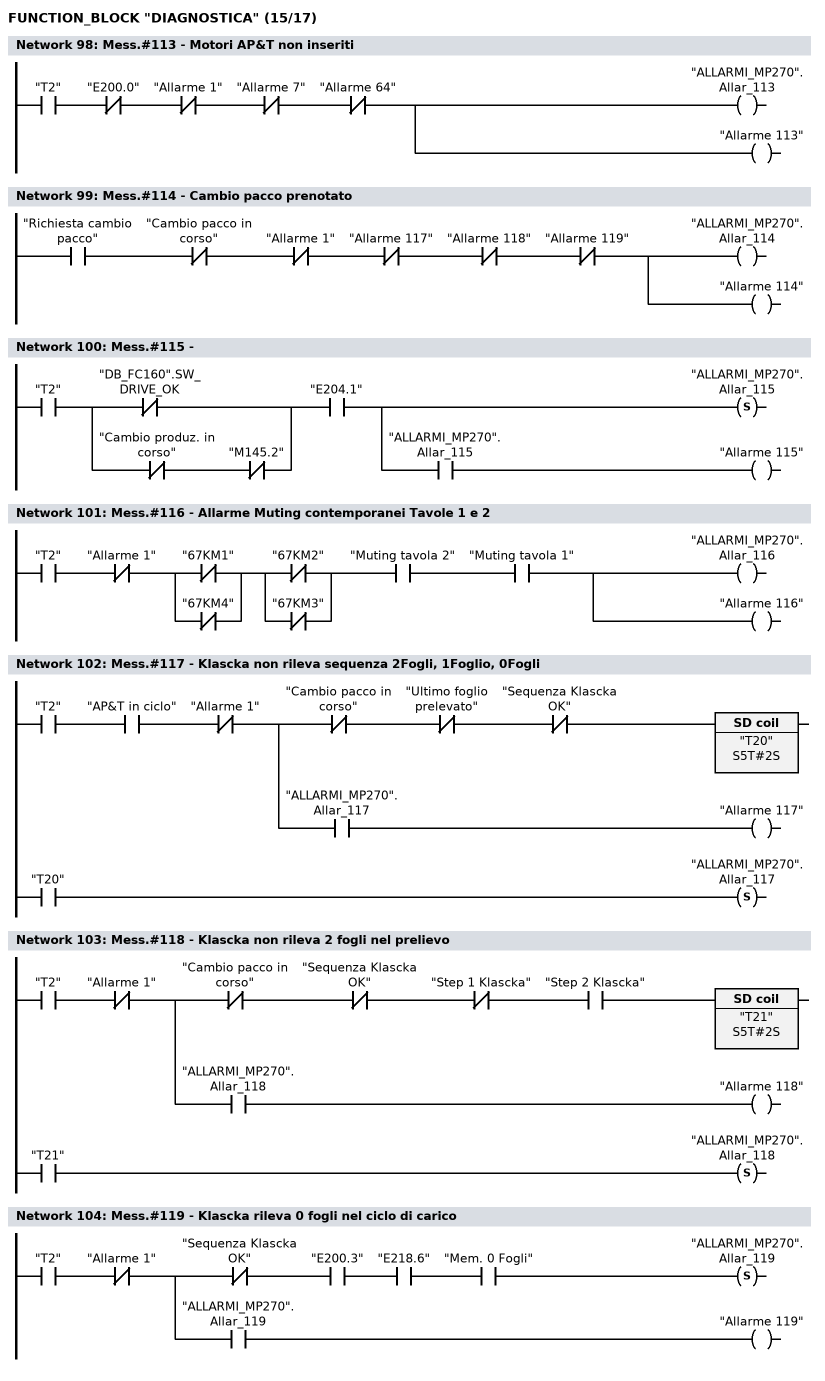
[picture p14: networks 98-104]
      U     "T2";
      UN    "E200.0";
      UN    "Allarme 1";
      UN    "Allarme 7";
      UN    "Allarme 64";
      =     "ALLARMI_MP270".Allar_113;
      =     "Allarme 113";
NETWORK
TITLE =Mess.#114 - Cambio pacco prenotato

      U     "Richiesta cambio pacco";
      UN    "Cambio pacco in corso";
      UN    "Allarme 1";
      UN    "Allarme 117";
      UN    "Allarme 118";
      UN    "Allarme 119";
      =     "ALLARMI_MP270".Allar_114;
      =     "Allarme 114";
NETWORK
TITLE =Mess.#115 -

      U     "T2";
      U(    ;
      ON    "DB_FC160".SW_DRIVE_OK;
      O     ;
      UN    "Cambio produz. in corso";
      UN    "M145.2";
      )     ;
      U     "E204.1";
      =     L      0.0;
      U     L      0.0;
      BLD   102;
      S     "ALLARMI_MP270".Allar_115;
      U     L      0.0;
      U     "ALLARMI_MP270".Allar_115;
      =     "Allarme 115";
NETWORK
TITLE =Mess.#116 - Allarme Muting contemporanei Tavole 1 e 2

      U     "T2";
      UN    "Allarme 1";
      U(    ;
      ON    "67KM1";
      ON    "67KM4";
      )     ;
      U(    ;
      ON    "67KM2";
      ON    "67KM3";
      )     ;
      U     "Muting tavola 2";
      U     "Muting tavola 1";
      =     "ALLARMI_MP270".Allar_116;
      =     "Allarme 116";
NETWORK
TITLE =Mess.#117 - Klascka non rileva sequenza 2Fogli, 1Foglio, 0Fogli

      U     "T2";
      U     "AP&T  in ciclo";
      UN    "Allarme 1";
      =     L      0.0;
      U     L      0.0;
      UN    "Cambio pacco in corso";
      UN    "Ultimo foglio prelevato";
      UN    "Sequenza Klascka OK";
      L     S5T#2S;
      SE    "T20";
      NOP   0;
      NOP   0;
      NOP   0;
      U     "T20";
      S     "ALLARMI_MP270".Allar_117;
      U     L      0.0;
      U     "ALLARMI_MP270".Allar_117;
      =     "Allarme 117";
NETWORK
TITLE =Mess.#118 - Klascka non rileva 2 fogli nel prelievo

      U     "T2";
      UN    "Allarme 1";
      =     L      0.0;
      U     L      0.0;
      UN    "Cambio pacco in corso";
      UN    "Sequenza Klascka OK";
      UN    "Step 1   Klascka";
      U     "Step 2   Klascka";
      L     S5T#2S;
      SE    "T21";
      NOP   0;
      NOP   0;
      NOP   0;
      U     "T21";
      S     "ALLARMI_MP270".Allar_118;
      U     L      0.0;
      U     "ALLARMI_MP270".Allar_118;
      =     "Allarme 118";
NETWORK
TITLE =Mess.#119 - Klascka rileva 0 fogli nel ciclo di carico

      U     "T2";
      UN    "Allarme 1";
      =     L      0.0;
      U     L      0.0;
      UN    "Sequenza Klascka OK";
      U     "E200.3";
      U     "E218.6";
      U     "Mem. 0 Fogli";
      S     "ALLARMI_MP270".Allar_119;
      U     L      0.0;
      U     "ALLARMI_MP270".Allar_119;
      =     "Allarme 119";
NETWORK
TITLE =Reset automatico in ciclo

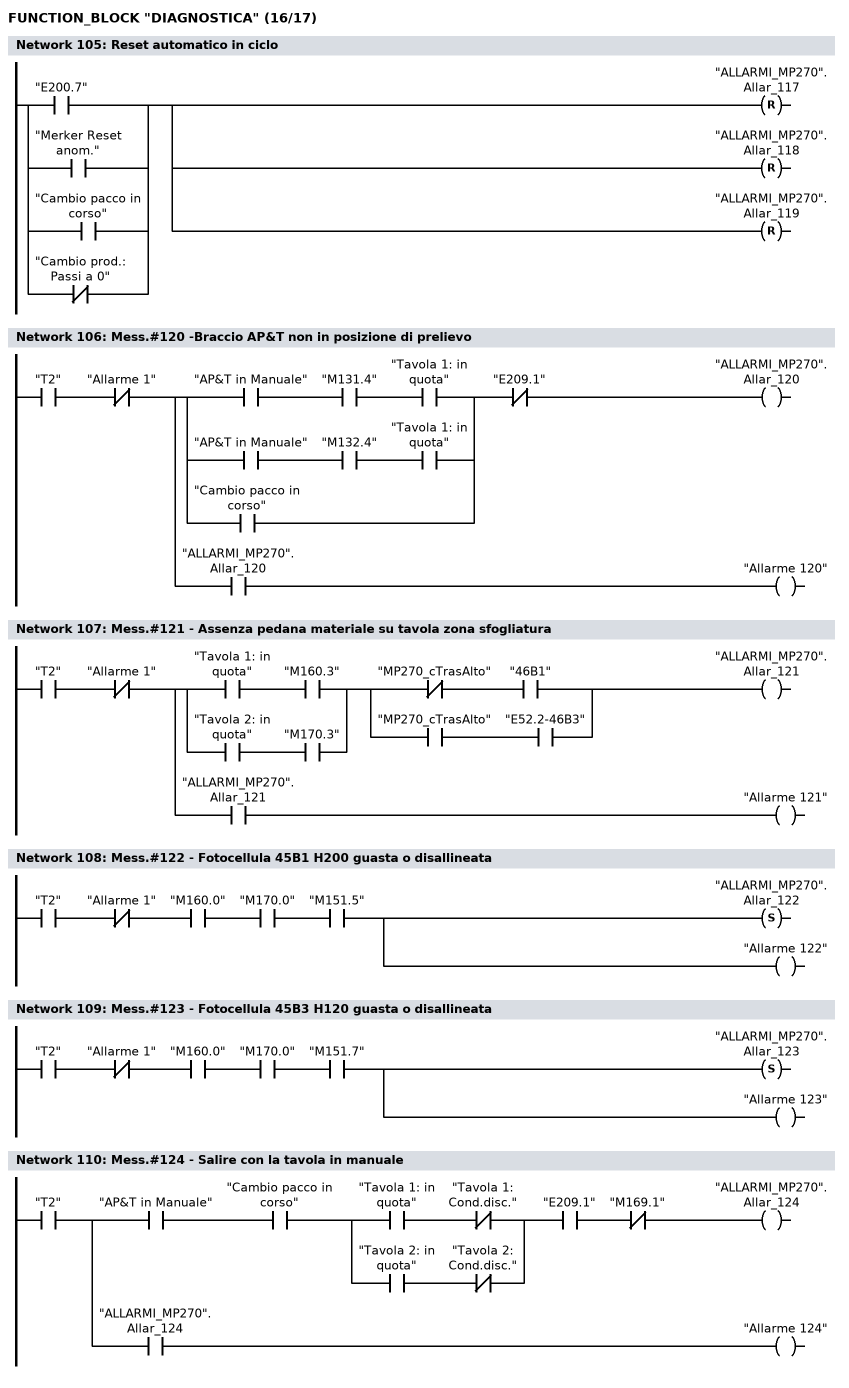
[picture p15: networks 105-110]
      O     "E200.7";
      O     "Merker Reset anom.";
      O     "Cambio pacco in corso";
      ON    "Cambio prod.: Passi a 0";
      R     "ALLARMI_MP270".Allar_117;
      R     "ALLARMI_MP270".Allar_118;
      R     "ALLARMI_MP270".Allar_119;
NETWORK
TITLE =Mess.#120 -Braccio AP&T non in posizione di prelievo

      U     "T2";
      UN    "Allarme 1";
      =     L      0.0;
      U     L      0.0;
      U(    ;
      U     "AP&T in Manuale";
      U     "M131.4";
      U     "Tavola 1: in quota";
      O     ;
      U     "AP&T in Manuale";
      U     "M132.4";
      U     "Tavola 1: in quota";
      O     "Cambio pacco in corso";
      )     ;
      UN    "E209.1";
      =     "ALLARMI_MP270".Allar_120;
      U     L      0.0;
      U     "ALLARMI_MP270".Allar_120;
      =     "Allarme 120";
NETWORK
TITLE =Mess.#121 - Assenza pedana materiale su tavola zona sfogliatura

      U     "T2";
      UN    "Allarme 1";
      =     L      0.0;
      U     L      0.0;
      U(    ;
      U     "Tavola 1: in quota";
      U     "M160.3";
      O     ;
      U     "Tavola 2: in quota";
      U     "M170.3";
      )     ;
      U(    ;
      UN    "MP270_cTrasAlto";
      U     "46B1";
      O     ;
      U     "MP270_cTrasAlto";
      U     "E52.2-46B3";
      )     ;
      =     "ALLARMI_MP270".Allar_121;
      U     L      0.0;
      U     "ALLARMI_MP270".Allar_121;
      =     "Allarme 121";
NETWORK
TITLE =Mess.#122 - Fotocellula 45B1 H200 guasta o disallineata

      U     "T2";
      UN    "Allarme 1";
      U     "M160.0";
      U     "M170.0";
      U     "M151.5";
      S     "ALLARMI_MP270".Allar_122;
      =     "Allarme 122";
NETWORK
TITLE =Mess.#123 - Fotocellula 45B3 H120 guasta o disallineata

      U     "T2";
      UN    "Allarme 1";
      U     "M160.0";
      U     "M170.0";
      U     "M151.7";
      S     "ALLARMI_MP270".Allar_123;
      =     "Allarme 123";
NETWORK
TITLE =Mess.#124 - Salire con la tavola in manuale

      U     "T2";
      =     L      0.0;
      U     L      0.0;
      U     "AP&T in Manuale";
      U     "Cambio pacco in corso";
      U(    ;
      U     "Tavola 1: in quota";
      UN    "Tavola 1: Cond.disc.";
      O     ;
      U     "Tavola 2: in quota";
      UN    "Tavola 2: Cond.disc.";
      )     ;
      U     "E209.1";
      UN    "M169.1";
      =     "ALLARMI_MP270".Allar_124;
      U     L      0.0;
      U     "ALLARMI_MP270".Allar_124;
      =     "Allarme 124";
NETWORK
TITLE =Mess.#125 - Anomalia dispositivo Klaska (cavo interrotto)

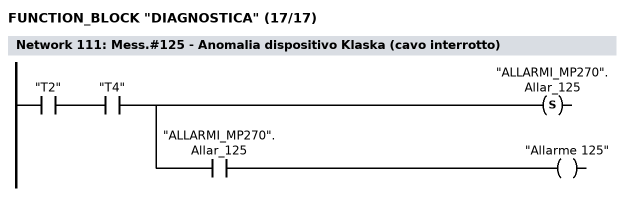
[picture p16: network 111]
      U     "T2";
      U     "T4";
      =     L      0.0;
      U     L      0.0;
      BLD   102;
      S     "ALLARMI_MP270".Allar_125;
      U     L      0.0;
      U     "ALLARMI_MP270".Allar_125;
      =     "Allarme 125";
NETWORK
TITLE =Mess.#126 - Time out Unita' di centraggio Bloccata

      U     "T2";
      =     L      0.0;
      U(    ;
      U     L      0.0;
      U     "75YV1A";
      UN    "M140.2";
      L     S5T#3S;
      SE    T     76;
      NOP   0;
      NOP   0;
      NOP   0;
      U     T     76;
      )     ;
      UN    "Allarme 1";
      =     "ALLARMI_MP270".Allar_126;
      U     L      0.0;
      U     "ALLARMI_MP270".Allar_126;
      =     "Allarme 126";
NETWORK
TITLE =Mess.#127 - Time out Unita' di centraggio sbloccata

      U     "T2";
      =     L      0.0;
      U(    ;
      U     L      0.0;
      U     "75YV1B";
      UN    "M140.3";
      L     S5T#3S;
      SE    "T77";
      NOP   0;
      NOP   0;
      NOP   0;
      U     "T77";
      )     ;
      UN    "Allarme 1";
      =     "ALLARMI_MP270".Allar_127;
      U     L      0.0;
      U     "ALLARMI_MP270".Allar_127;
      =     "Allarme 127";
NETWORK
TITLE =Mess.#128 - Magnetotermico trasformatore motori BRUSHLESS 12QF2

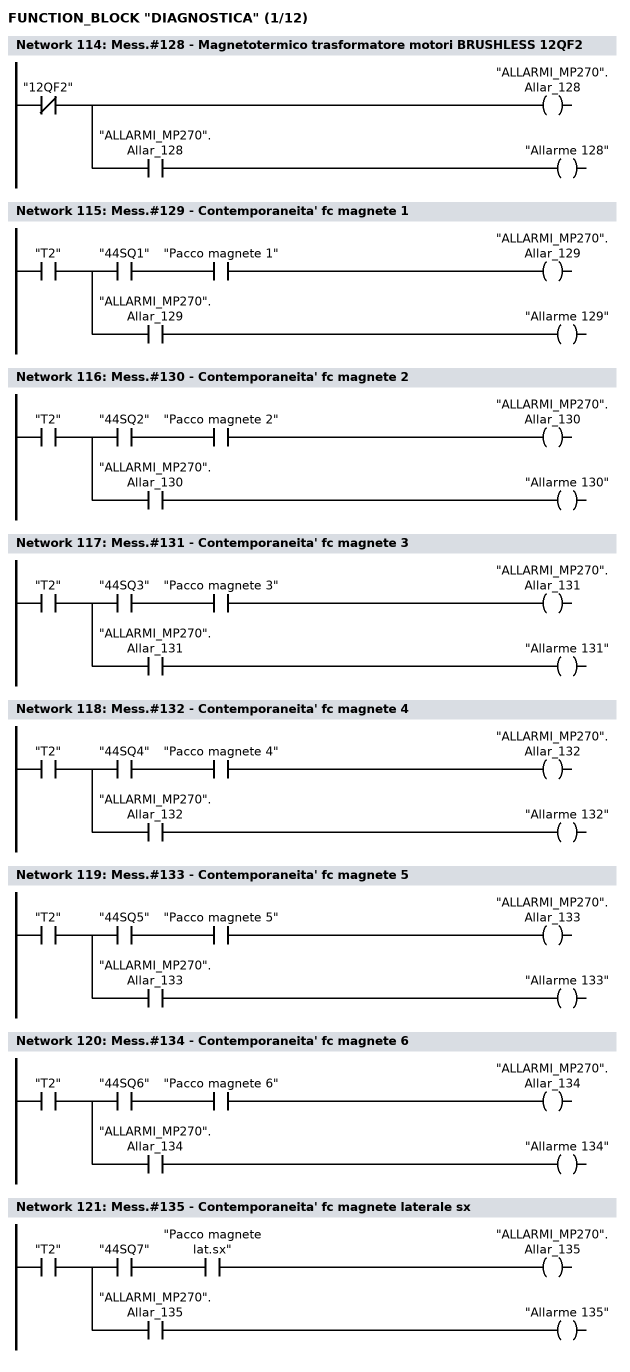
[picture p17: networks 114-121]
      UN    "12QF2";
      =     L      0.0;
      U     L      0.0;
      BLD   102;
      =     "ALLARMI_MP270".Allar_128;
      U     L      0.0;
      U     "ALLARMI_MP270".Allar_128;
      =     "Allarme 128";
NETWORK
TITLE =Mess.#129 - Contemporaneita' fc magnete 1

      U     "T2";
      =     L      0.0;
      U     L      0.0;
      U     "44SQ1";
      U     "Pacco magnete 1";
      =     "ALLARMI_MP270".Allar_129;
      U     L      0.0;
      U     "ALLARMI_MP270".Allar_129;
      =     "Allarme 129";
NETWORK
TITLE =Mess.#130 - Contemporaneita' fc magnete 2

      U     "T2";
      =     L      0.0;
      U     L      0.0;
      U     "44SQ2";
      U     "Pacco magnete 2";
      =     "ALLARMI_MP270".Allar_130;
      U     L      0.0;
      U     "ALLARMI_MP270".Allar_130;
      =     "Allarme 130";
NETWORK
TITLE =Mess.#131 - Contemporaneita' fc magnete 3

      U     "T2";
      =     L      0.0;
      U     L      0.0;
      U     "44SQ3";
      U     "Pacco magnete 3";
      =     "ALLARMI_MP270".Allar_131;
      U     L      0.0;
      U     "ALLARMI_MP270".Allar_131;
      =     "Allarme 131";
NETWORK
TITLE =Mess.#132 - Contemporaneita' fc magnete 4

      U     "T2";
      =     L      0.0;
      U     L      0.0;
      U     "44SQ4";
      U     "Pacco magnete 4";
      =     "ALLARMI_MP270".Allar_132;
      U     L      0.0;
      U     "ALLARMI_MP270".Allar_132;
      =     "Allarme 132";
NETWORK
TITLE =Mess.#133 - Contemporaneita' fc magnete 5

      U     "T2";
      =     L      0.0;
      U     L      0.0;
      U     "44SQ5";
      U     "Pacco magnete 5";
      =     "ALLARMI_MP270".Allar_133;
      U     L      0.0;
      U     "ALLARMI_MP270".Allar_133;
      =     "Allarme 133";
NETWORK
TITLE =Mess.#134 - Contemporaneita' fc magnete 6

      U     "T2";
      =     L      0.0;
      U     L      0.0;
      U     "44SQ6";
      U     "Pacco magnete 6";
      =     "ALLARMI_MP270".Allar_134;
      U     L      0.0;
      U     "ALLARMI_MP270".Allar_134;
      =     "Allarme 134";
NETWORK
TITLE =Mess.#135 - Contemporaneita' fc magnete laterale sx

      U     "T2";
      =     L      0.0;
      U     L      0.0;
      U     "44SQ7";
      U     "Pacco magnete lat.sx";
      =     "ALLARMI_MP270".Allar_135;
      U     L      0.0;
      U     "ALLARMI_MP270".Allar_135;
      =     "Allarme 135";
NETWORK
TITLE =Mess.#136 - Contemporaneita' fc magnete laterale dx

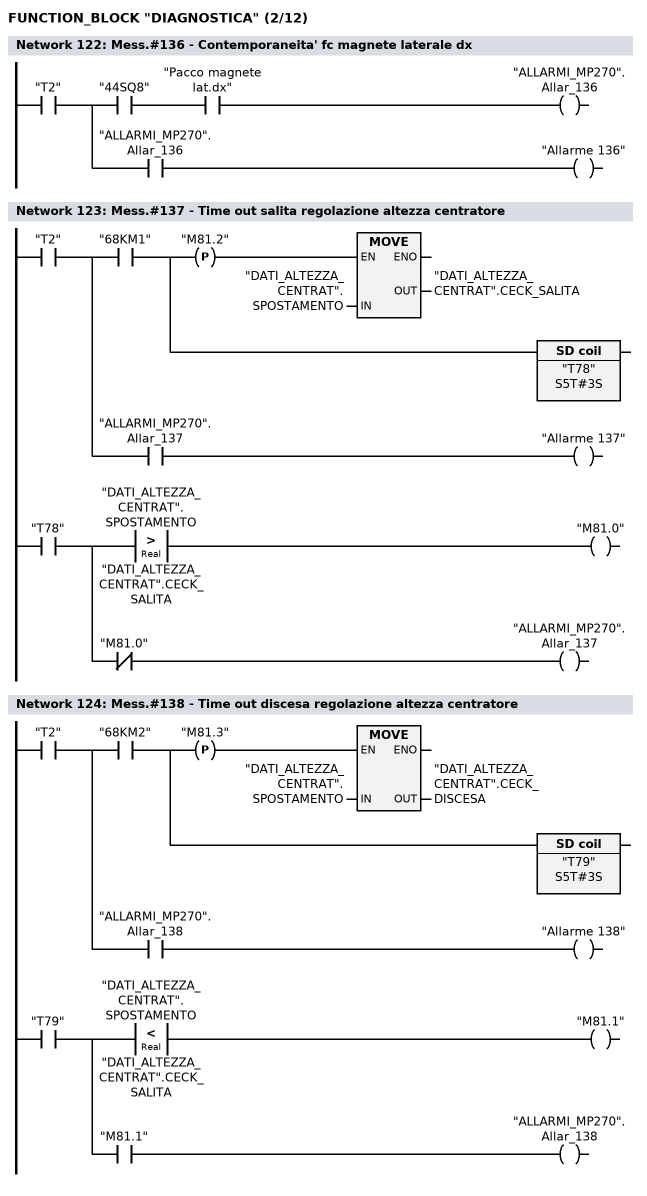
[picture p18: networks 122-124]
      U     "T2";
      =     L      0.0;
      U     L      0.0;
      U     "44SQ8";
      U     "Pacco magnete lat.dx";
      =     "ALLARMI_MP270".Allar_136;
      U     L      0.0;
      U     "ALLARMI_MP270".Allar_136;
      =     "Allarme 136";
NETWORK
TITLE =Mess.#137 - Time out salita regolazione altezza centratore

      U     "T2";
      =     L      0.0;
      U     L      0.0;
      U     "68KM1";
      =     L      0.1;
      U     L      0.1;
      FP    "M81.2";
      SPBNB _003;
      L     "DATI_ALTEZZA_CENTRAT".SPOSTAMENTO;
      T     "DATI_ALTEZZA_CENTRAT".CECK_SALITA;
_003: NOP   0;
      U     L      0.1;
      L     S5T#3S;
      SE    "T78";
      NOP   0;
      NOP   0;
      NOP   0;
      U     "T78";
      =     L      0.2;
      U     L      0.2;
      U(    ;
      L     "DATI_ALTEZZA_CENTRAT".SPOSTAMENTO;
      L     "DATI_ALTEZZA_CENTRAT".CECK_SALITA;
      >R    ;
      )     ;
      =     "M81.0";
      U     L      0.2;
      UN    "M81.0";
      =     "ALLARMI_MP270".Allar_137;
      U     L      0.0;
      U     "ALLARMI_MP270".Allar_137;
      =     "Allarme 137";
NETWORK
TITLE =Mess.#138 - Time out discesa regolazione altezza centratore

      U     "T2";
      =     L      0.0;
      U     L      0.0;
      U     "68KM2";
      =     L      0.1;
      U     L      0.1;
      FP    "M81.3";
      SPBNB _004;
      L     "DATI_ALTEZZA_CENTRAT".SPOSTAMENTO;
      T     "DATI_ALTEZZA_CENTRAT".CECK_DISCESA;
_004: NOP   0;
      U     L      0.1;
      L     S5T#3S;
      SE    "T79";
      NOP   0;
      NOP   0;
      NOP   0;
      U     "T79";
      =     L      0.2;
      U     L      0.2;
      U(    ;
      L     "DATI_ALTEZZA_CENTRAT".SPOSTAMENTO;
      L     "DATI_ALTEZZA_CENTRAT".CECK_SALITA;
      <R    ;
      )     ;
      =     "M81.1";
      U     L      0.2;
      U     "M81.1";
      =     "ALLARMI_MP270".Allar_138;
      U     L      0.0;
      U     "ALLARMI_MP270".Allar_138;
      =     "Allarme 138";
NETWORK
TITLE =Mess.#139 - Time out centratore verso pressa

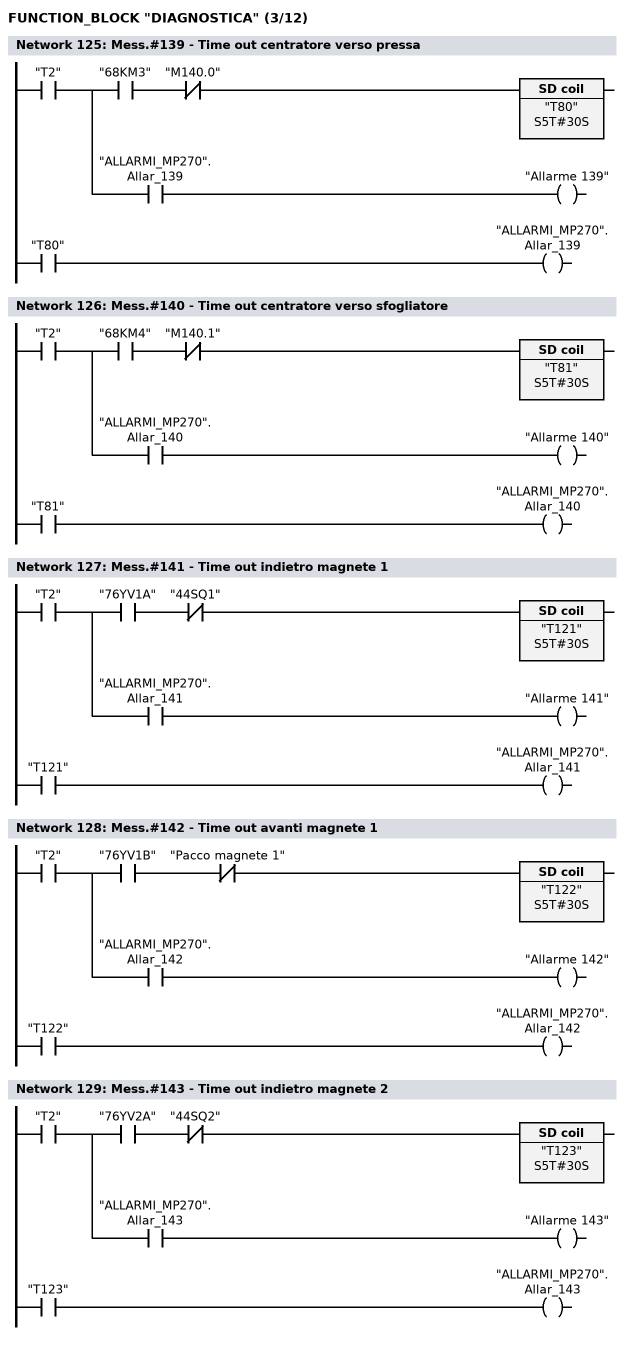
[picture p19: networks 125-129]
      U     "T2";
      =     L      0.0;
      U     L      0.0;
      U     "68KM3";
      UN    "M140.0";
      L     S5T#30S;
      SE    "T80";
      NOP   0;
      NOP   0;
      NOP   0;
      U     "T80";
      =     "ALLARMI_MP270".Allar_139;
      U     L      0.0;
      U     "ALLARMI_MP270".Allar_139;
      =     "Allarme 139";
NETWORK
TITLE =Mess.#140 - Time out centratore verso sfogliatore

      U     "T2";
      =     L      0.0;
      U     L      0.0;
      U     "68KM4";
      UN    "M140.1";
      L     S5T#30S;
      SE    "T81";
      NOP   0;
      NOP   0;
      NOP   0;
      U     "T81";
      =     "ALLARMI_MP270".Allar_140;
      U     L      0.0;
      U     "ALLARMI_MP270".Allar_140;
      =     "Allarme 140";
NETWORK
TITLE =Mess.#141 - Time out indietro magnete 1

      U     "T2";
      =     L      0.0;
      U     L      0.0;
      U     "76YV1A";
      UN    "44SQ1";
      L     S5T#30S;
      SE    "T121";
      NOP   0;
      NOP   0;
      NOP   0;
      U     "T121";
      =     "ALLARMI_MP270".Allar_141;
      U     L      0.0;
      U     "ALLARMI_MP270".Allar_141;
      =     "Allarme 141";
NETWORK
TITLE =Mess.#142 - Time out avanti magnete 1

      U     "T2";
      =     L      0.0;
      U     L      0.0;
      U     "76YV1B";
      UN    "Pacco magnete 1";
      L     S5T#30S;
      SE    "T122";
      NOP   0;
      NOP   0;
      NOP   0;
      U     "T122";
      =     "ALLARMI_MP270".Allar_142;
      U     L      0.0;
      U     "ALLARMI_MP270".Allar_142;
      =     "Allarme 142";
NETWORK
TITLE =Mess.#143 - Time out indietro magnete 2

      U     "T2";
      =     L      0.0;
      U     L      0.0;
      U     "76YV2A";
      UN    "44SQ2";
      L     S5T#30S;
      SE    "T123";
      NOP   0;
      NOP   0;
      NOP   0;
      U     "T123";
      =     "ALLARMI_MP270".Allar_143;
      U     L      0.0;
      U     "ALLARMI_MP270".Allar_143;
      =     "Allarme 143";
NETWORK
TITLE =Mess.#144 - Time out avanti magnete 2

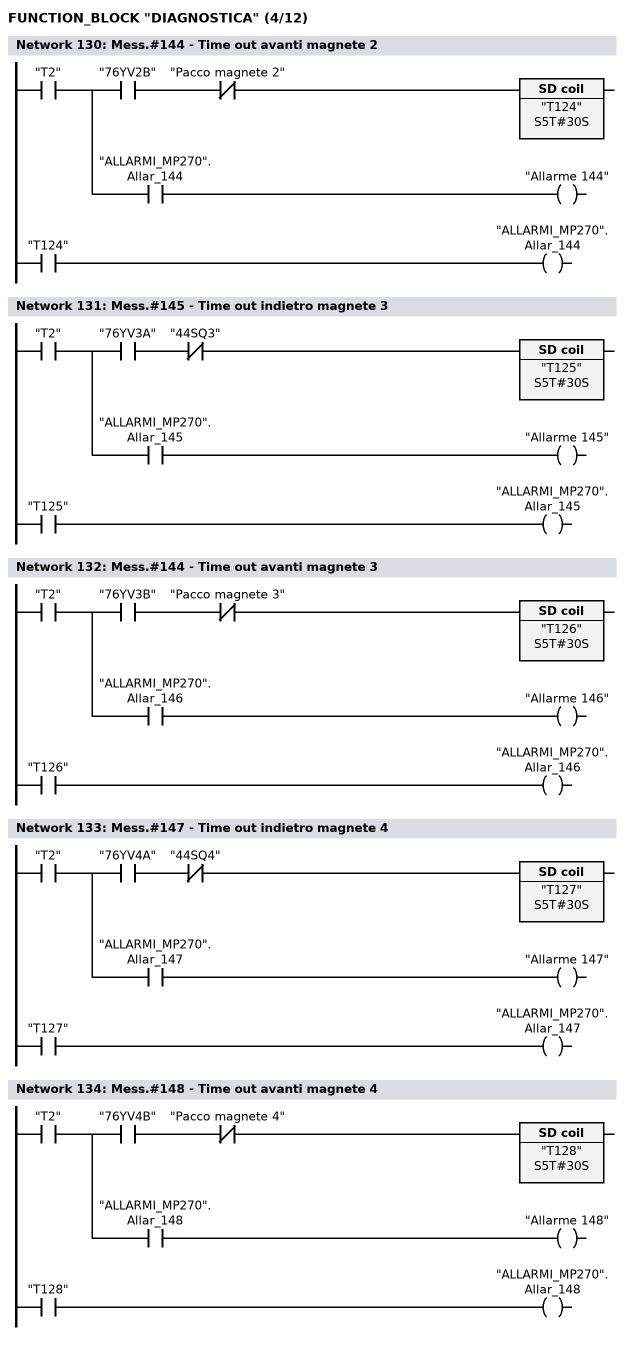
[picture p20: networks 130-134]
      U     "T2";
      =     L      0.0;
      U     L      0.0;
      U     "76YV2B";
      UN    "Pacco magnete 2";
      L     S5T#30S;
      SE    "T124";
      NOP   0;
      NOP   0;
      NOP   0;
      U     "T124";
      =     "ALLARMI_MP270".Allar_144;
      U     L      0.0;
      U     "ALLARMI_MP270".Allar_144;
      =     "Allarme 144";
NETWORK
TITLE =Mess.#145 - Time out indietro magnete 3

      U     "T2";
      =     L      0.0;
      U     L      0.0;
      U     "76YV3A";
      UN    "44SQ3";
      L     S5T#30S;
      SE    "T125";
      NOP   0;
      NOP   0;
      NOP   0;
      U     "T125";
      =     "ALLARMI_MP270".Allar_145;
      U     L      0.0;
      U     "ALLARMI_MP270".Allar_145;
      =     "Allarme 145";
NETWORK
TITLE =Mess.#144 - Time out avanti magnete 3

      U     "T2";
      =     L      0.0;
      U     L      0.0;
      U     "76YV3B";
      UN    "Pacco magnete 3";
      L     S5T#30S;
      SE    "T126";
      NOP   0;
      NOP   0;
      NOP   0;
      U     "T126";
      =     "ALLARMI_MP270".Allar_146;
      U     L      0.0;
      U     "ALLARMI_MP270".Allar_146;
      =     "Allarme 146";
NETWORK
TITLE =Mess.#147 - Time out indietro magnete 4

      U     "T2";
      =     L      0.0;
      U     L      0.0;
      U     "76YV4A";
      UN    "44SQ4";
      L     S5T#30S;
      SE    "T127";
      NOP   0;
      NOP   0;
      NOP   0;
      U     "T127";
      =     "ALLARMI_MP270".Allar_147;
      U     L      0.0;
      U     "ALLARMI_MP270".Allar_147;
      =     "Allarme 147";
NETWORK
TITLE =Mess.#148 - Time out avanti magnete 4

      U     "T2";
      =     L      0.0;
      U     L      0.0;
      U     "76YV4B";
      UN    "Pacco magnete 4";
      L     S5T#30S;
      SE    "T128";
      NOP   0;
      NOP   0;
      NOP   0;
      U     "T128";
      =     "ALLARMI_MP270".Allar_148;
      U     L      0.0;
      U     "ALLARMI_MP270".Allar_148;
      =     "Allarme 148";
NETWORK
TITLE =Mess.#149 - Time out indietro magnete 5

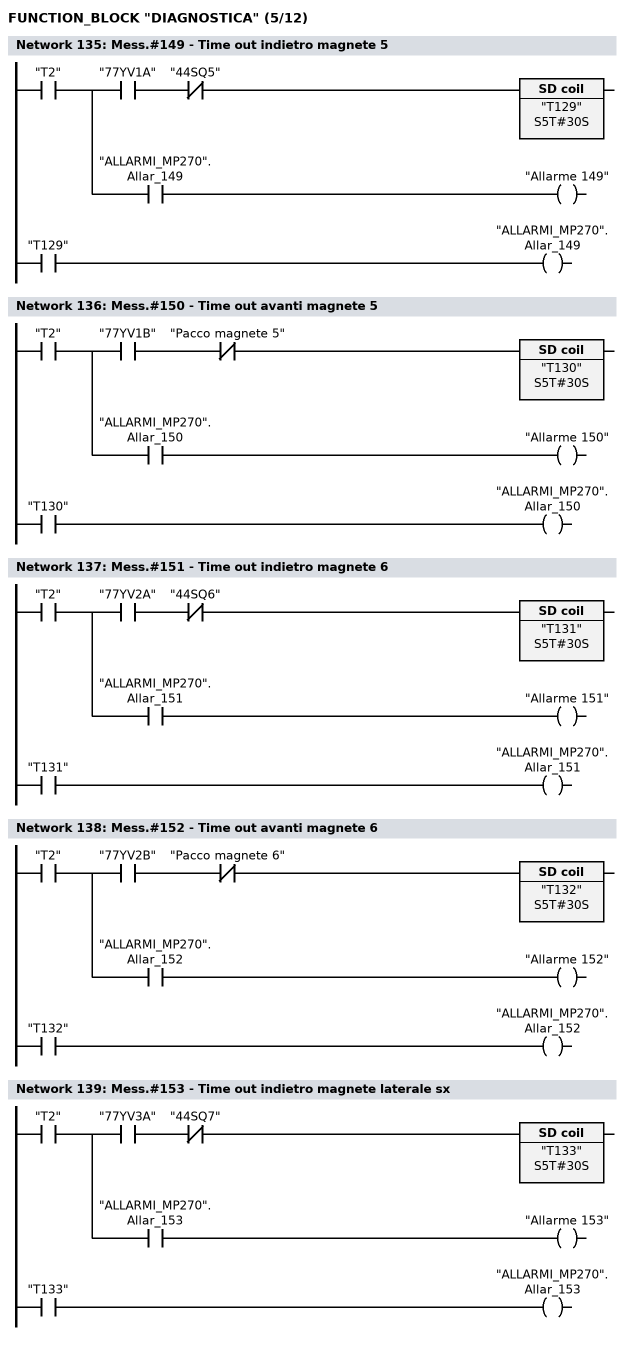
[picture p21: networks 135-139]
      U     "T2";
      =     L      0.0;
      U     L      0.0;
      U     "77YV1A";
      UN    "44SQ5";
      L     S5T#30S;
      SE    "T129";
      NOP   0;
      NOP   0;
      NOP   0;
      U     "T129";
      =     "ALLARMI_MP270".Allar_149;
      U     L      0.0;
      U     "ALLARMI_MP270".Allar_149;
      =     "Allarme 149";
NETWORK
TITLE =Mess.#150 - Time out avanti magnete 5

      U     "T2";
      =     L      0.0;
      U     L      0.0;
      U     "77YV1B";
      UN    "Pacco magnete 5";
      L     S5T#30S;
      SE    "T130";
      NOP   0;
      NOP   0;
      NOP   0;
      U     "T130";
      =     "ALLARMI_MP270".Allar_150;
      U     L      0.0;
      U     "ALLARMI_MP270".Allar_150;
      =     "Allarme 150";
NETWORK
TITLE =Mess.#151 - Time out indietro magnete 6

      U     "T2";
      =     L      0.0;
      U     L      0.0;
      U     "77YV2A";
      UN    "44SQ6";
      L     S5T#30S;
      SE    "T131";
      NOP   0;
      NOP   0;
      NOP   0;
      U     "T131";
      =     "ALLARMI_MP270".Allar_151;
      U     L      0.0;
      U     "ALLARMI_MP270".Allar_151;
      =     "Allarme 151";
NETWORK
TITLE =Mess.#152 - Time out avanti magnete 6

      U     "T2";
      =     L      0.0;
      U     L      0.0;
      U     "77YV2B";
      UN    "Pacco magnete 6";
      L     S5T#30S;
      SE    "T132";
      NOP   0;
      NOP   0;
      NOP   0;
      U     "T132";
      =     "ALLARMI_MP270".Allar_152;
      U     L      0.0;
      U     "ALLARMI_MP270".Allar_152;
      =     "Allarme 152";
NETWORK
TITLE =Mess.#153 - Time out indietro magnete laterale sx

      U     "T2";
      =     L      0.0;
      U     L      0.0;
      U     "77YV3A";
      UN    "44SQ7";
      L     S5T#30S;
      SE    "T133";
      NOP   0;
      NOP   0;
      NOP   0;
      U     "T133";
      =     "ALLARMI_MP270".Allar_153;
      U     L      0.0;
      U     "ALLARMI_MP270".Allar_153;
      =     "Allarme 153";
NETWORK
TITLE =Mess.#154 - Time out avanti magnete laterale sx

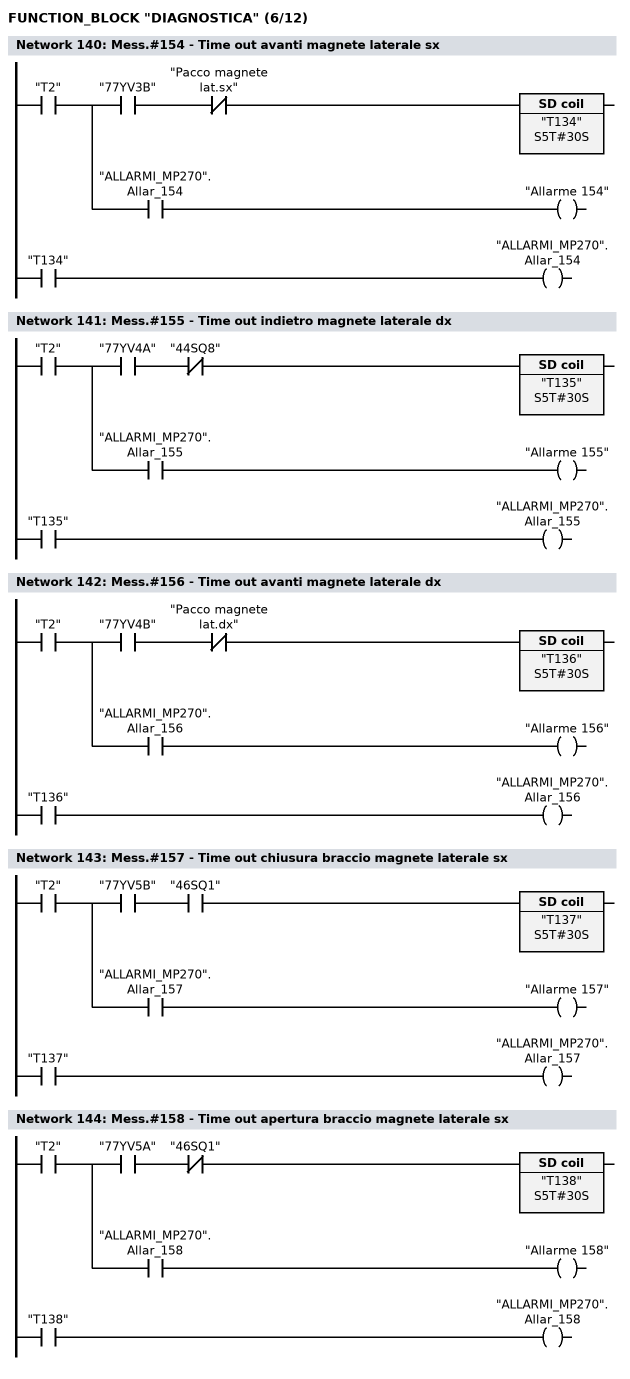
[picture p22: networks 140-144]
      U     "T2";
      =     L      0.0;
      U     L      0.0;
      U     "77YV3B";
      UN    "Pacco magnete lat.sx";
      L     S5T#30S;
      SE    "T134";
      NOP   0;
      NOP   0;
      NOP   0;
      U     "T134";
      =     "ALLARMI_MP270".Allar_154;
      U     L      0.0;
      U     "ALLARMI_MP270".Allar_154;
      =     "Allarme 154";
NETWORK
TITLE =Mess.#155 - Time out indietro magnete laterale dx

      U     "T2";
      =     L      0.0;
      U     L      0.0;
      U     "77YV4A";
      UN    "44SQ8";
      L     S5T#30S;
      SE    "T135";
      NOP   0;
      NOP   0;
      NOP   0;
      U     "T135";
      =     "ALLARMI_MP270".Allar_155;
      U     L      0.0;
      U     "ALLARMI_MP270".Allar_155;
      =     "Allarme 155";
NETWORK
TITLE =Mess.#156 - Time out avanti magnete laterale dx

      U     "T2";
      =     L      0.0;
      U     L      0.0;
      U     "77YV4B";
      UN    "Pacco magnete lat.dx";
      L     S5T#30S;
      SE    "T136";
      NOP   0;
      NOP   0;
      NOP   0;
      U     "T136";
      =     "ALLARMI_MP270".Allar_156;
      U     L      0.0;
      U     "ALLARMI_MP270".Allar_156;
      =     "Allarme 156";
NETWORK
TITLE =Mess.#157 - Time out chiusura braccio magnete laterale sx

      U     "T2";
      =     L      0.0;
      U     L      0.0;
      U     "77YV5B";
      U     "46SQ1";
      L     S5T#30S;
      SE    "T137";
      NOP   0;
      NOP   0;
      NOP   0;
      U     "T137";
      =     "ALLARMI_MP270".Allar_157;
      U     L      0.0;
      U     "ALLARMI_MP270".Allar_157;
      =     "Allarme 157";
NETWORK
TITLE =Mess.#158 - Time out apertura braccio magnete laterale sx

      U     "T2";
      =     L      0.0;
      U     L      0.0;
      U     "77YV5A";
      UN    "46SQ1";
      L     S5T#30S;
      SE    "T138";
      NOP   0;
      NOP   0;
      NOP   0;
      U     "T138";
      =     "ALLARMI_MP270".Allar_158;
      U     L      0.0;
      U     "ALLARMI_MP270".Allar_158;
      =     "Allarme 158";
NETWORK
TITLE =Mess.#159 - Time out chiusura braccio magnete laterale dx

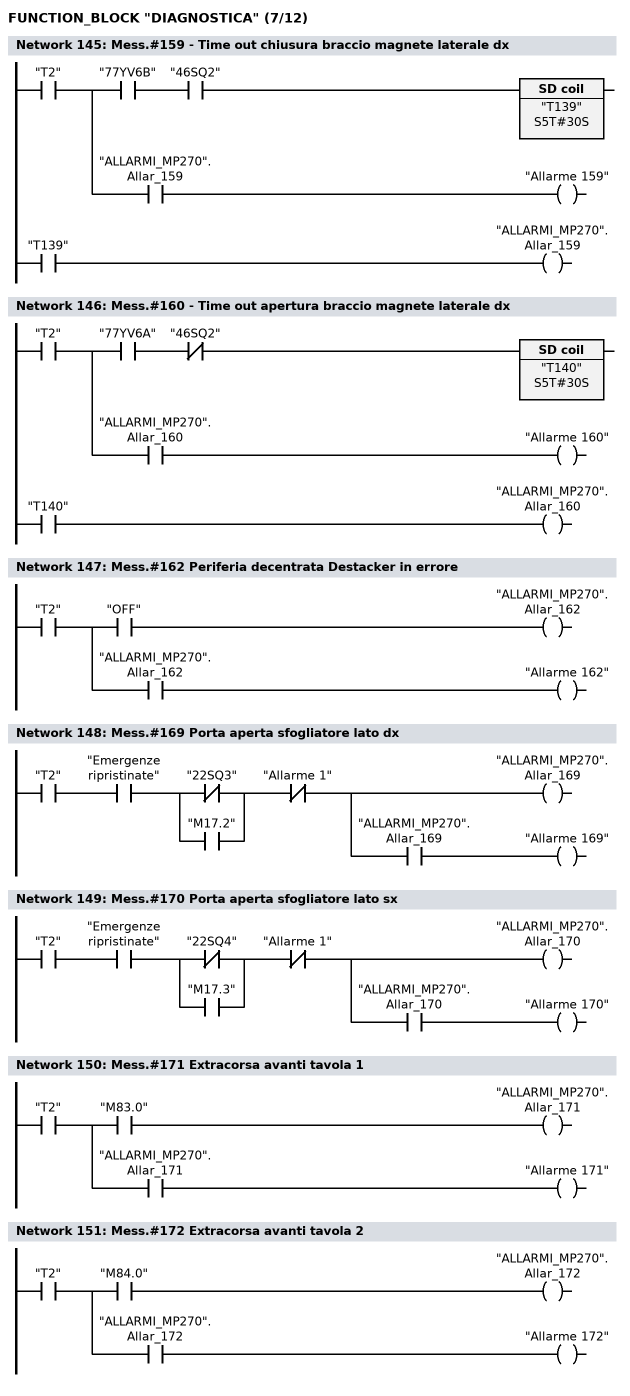
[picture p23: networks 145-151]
      U     "T2";
      =     L      0.0;
      U     L      0.0;
      U     "77YV6B";
      U     "46SQ2";
      L     S5T#30S;
      SE    "T139";
      NOP   0;
      NOP   0;
      NOP   0;
      U     "T139";
      =     "ALLARMI_MP270".Allar_159;
      U     L      0.0;
      U     "ALLARMI_MP270".Allar_159;
      =     "Allarme 159";
NETWORK
TITLE =Mess.#160 - Time out apertura braccio magnete laterale dx

      U     "T2";
      =     L      0.0;
      U     L      0.0;
      U     "77YV6A";
      UN    "46SQ2";
      L     S5T#30S;
      SE    "T140";
      NOP   0;
      NOP   0;
      NOP   0;
      U     "T140";
      =     "ALLARMI_MP270".Allar_160;
      U     L      0.0;
      U     "ALLARMI_MP270".Allar_160;
      =     "Allarme 160";
NETWORK
TITLE =Mess.#162 Periferia decentrata Destacker in errore

      U     "T2";
      =     L      0.0;
      U     L      0.0;
      U     "OFF";
      =     "ALLARMI_MP270".Allar_162;
      U     L      0.0;
      U     "ALLARMI_MP270".Allar_162;
      =     "Allarme 162";
NETWORK
TITLE =Mess.#169 Porta aperta sfogliatore lato dx

      U     "T2";
      U     "Emergenze ripristinate";
      U(    ;
      ON    "22SQ3";
      O     "M17.2";
      )     ;
      UN    "Allarme 1";
      =     L      0.0;
      U     L      0.0;
      BLD   102;
      =     "ALLARMI_MP270".Allar_169;
      U     L      0.0;
      U     "ALLARMI_MP270".Allar_169;
      =     "Allarme 169";
NETWORK
TITLE =Mess.#170 Porta aperta sfogliatore lato sx

      U     "T2";
      U     "Emergenze ripristinate";
      U(    ;
      ON    "22SQ4";
      O     "M17.3";
      )     ;
      UN    "Allarme 1";
      =     L      0.0;
      U     L      0.0;
      BLD   102;
      =     "ALLARMI_MP270".Allar_170;
      U     L      0.0;
      U     "ALLARMI_MP270".Allar_170;
      =     "Allarme 170";
NETWORK
TITLE =Mess.#171 Extracorsa avanti tavola 1

      U     "T2";
      =     L      0.0;
      U     L      0.0;
      U     "M83.0";
      =     "ALLARMI_MP270".Allar_171;
      U     L      0.0;
      U     "ALLARMI_MP270".Allar_171;
      =     "Allarme 171";
NETWORK
TITLE =Mess.#172 Extracorsa avanti tavola 2

      U     "T2";
      =     L      0.0;
      U     L      0.0;
      U     "M84.0";
      =     "ALLARMI_MP270".Allar_172;
      U     L      0.0;
      U     "ALLARMI_MP270".Allar_172;
      =     "Allarme 172";
NETWORK
TITLE =Mess.#173 Extracorsa indietro tavola 1

      U     "T2";
      =     L      0.0;
      U     L      0.0;
      U     "M83.1";
      =     "ALLARMI_MP270".Allar_173;
      U     L      0.0;
      U     "ALLARMI_MP270".Allar_173;
      =     "Allarme 173";
NETWORK
TITLE =Mess.#174 Extracorsa indietro tavola 2

      U     "T2";
      =     L      0.0;
      U     L      0.0;
      U     "M84.1";
      =     "ALLARMI_MP270".Allar_174;
      U     L      0.0;
      U     "ALLARMI_MP270".Allar_174;
      =     "Allarme 174";
NETWORK
TITLE =Mess.#175 Emergenza AP&T

      U     "T2";
      =     L      0.0;
      U     L      0.0;
      UN    "Emerg.AP&T ok";
      =     "ALLARMI_MP270".Allar_175;
      U     L      0.0;
      U     "ALLARMI_MP270".Allar_175;
      =     "Allarme 175";
NETWORK
TITLE =Mess.#176 Extracorsa incremento pacco (fc su braccio AP&T)

      U     "T2";
      =     L      0.0;
      U     L      0.0;
      UN    "A23.6";
      U(    ;
      O     "STOP salita Tav. 1";
      O     "STOP salita Tav. 2";
      )     ;
      =     "ALLARMI_MP270".Allar_176;
      U     L      0.0;
      U     "ALLARMI_MP270".Allar_176;
      =     "Allarme 176";
NETWORK
TITLE =Mess.#177 Tavola 1 piena in uscita

      U     "T2";
      =     L      0.0;
      U     L      0.0;
      U     "Tavola 1: Piena in usc.";
      =     "ALLARMI_MP270".Allar_177;
      U     L      0.0;
      U     "ALLARMI_MP270".Allar_177;
      =     "Allarme 177";
NETWORK
TITLE =Mess.#178  Tavola 2 piena in uscita

      U     "T2";
      =     L      0.0;
      U     L      0.0;
      U     "Tavola 2: Piena in usc.";
      =     "ALLARMI_MP270".Allar_178;
      U     L      0.0;
      U     "ALLARMI_MP270".Allar_178;
      =     "Allarme 178";
NETWORK
TITLE =Mess.#179 Retrofitting rele' ciclo automatico

      U     "T2";
      =     L      0.0;
      U     L      0.0;
      U(    ;
      U     "25KA5";
      U     "25KA6";
      U     "Retrofitt. Automatico";
      O     ;
      UN    "25KA5";
      UN    "25KA6";
      UN    "Retrofitt. Automatico";
      )     ;
      L     S5T#1S;
      SE    "T30";
      NOP   0;
      NOP   0;
      NOP   0;
      U     "T30";
      =     "ALLARMI_MP270".Allar_179;
      U     L      0.0;
      U     "ALLARMI_MP270".Allar_179;
      =     "Allarme 179";
NETWORK
TITLE =Mess.#180 Retrofitting rele' ripari/barriere destacker

      U     "T2";
      =     L      0.0;
      U     L      0.0;
      U(    ;
      U     "25KA3";
      U     "25KA4";
      U     "Retrofitt. Ripari";
      O     ;
      UN    "25KA3";
      UN    "25KA4";
      UN    "Retrofitt. Ripari";
      )     ;
      L     S5T#1S;
      SE    "T31";
      NOP   0;
      NOP   0;
      NOP   0;
      U     "T31";
      S     "ALLARMI_MP270".Allar_180;
      U     L      0.0;
      U     "ALLARMI_MP270".Allar_180;
      =     "Allarme 180";
NETWORK
TITLE =Mess.#181 Retrofitting rele' start pressa (per comau)

      U     "T2";
      =     L      0.0;
      U     L      0.0;
      U(    ;
      U     "25KA7";
      U     "25KA8";
      U     "Retrofitt. Start Pressa";
      O     ;
      UN    "25KA7";
      UN    "25KA8";
      UN    "Retrofitt. Start Pressa";
      )     ;
      L     S5T#1S;
      SE    "T32";
      NOP   0;
      NOP   0;
      NOP   0;
      U     "T32";
      S     "ALLARMI_MP270".Allar_181;
      U     L      0.0;
      U     "ALLARMI_MP270".Allar_181;
      =     "Allarme 181";
NETWORK
TITLE =Mess.#182 Retrofitting Rele' emergenza Destaker

      U     "T2";
      =     L      0.0;
      U     L      0.0;
      U(    ;
      U     "25KA1";
      U     "25KA2";
      U     "Retrofitt. Emerg.riprist";
      O     ;
      UN    "25KA1";
      UN    "25KA2";
      UN    "Retrofitt. Emerg.riprist";
      )     ;
      L     S5T#1S;
      SE    "T33";
      NOP   0;
      NOP   0;
      NOP   0;
      U     "T33";
      S     "ALLARMI_MP270".Allar_182;
      U     L      0.0;
      U     "ALLARMI_MP270".Allar_182;
      =     "Allarme 182";
NETWORK
TITLE =Mess.#183 Retrofitting anticollisione/antischiacciamento tavole

      U     "T2";
      =     L      0.0;
      U     L      0.0;
      U(    ;
      U     "25KA9";
      U     "25KA10";
      U     "Retrofitt. Antisch/Antic";
      O     ;
      UN    "25KA9";
      UN    "25KA10";
      UN    "Retrofitt. Antisch/Antic";
      )     ;
      L     S5T#1S;
      SE    "T34";
      NOP   0;
      NOP   0;
      NOP   0;
      U     "T34";
      S     "ALLARMI_MP270".Allar_183;
      U     L      0.0;
      U     "ALLARMI_MP270".Allar_183;
      =     "Allarme 183";
NETWORK
TITLE =Mess.#184 Retrofitting override barriere

      U     "T2";
      =     L      0.0;
      U     L      0.0;
      U(    ;
      U     "25KA11";
      U     "25KA12";
      U     "Retrofitt. Override";
      O     ;
      UN    "25KA11";
      UN    "25KA12";
      UN    "Retrofitt. Override";
      )     ;
      L     S5T#1S;
      SE    "T35";
      NOP   0;
      NOP   0;
      NOP   0;
      U     "T35";
      S     "ALLARMI_MP270".Allar_184;
      U     L      0.0;
      U     "ALLARMI_MP270".Allar_184;
      =     "Allarme 184";
NETWORK
TITLE =Mess.#185 Attenzione dovresti aprire i centraggi

      U     "T2";
      =     L      0.0;
      U     L      0.0;
      U(    ;
      O     "M139.6";
      O     "M130.2";
      O     "M139.7";
      O     "M130.3";
      )     ;
      U     "AP&T in Manuale";
      U     "E219.5";
      UN    "Centratori tutti aperti";
      S     "ALLARMI_MP270".Allar_185;
      U     L      0.0;
      U(    ;
      O     "Centratori tutti aperti";
      O     "Merker Reset anom.";
      )     ;
      R     "ALLARMI_MP270".Allar_185;
      U     L      0.0;
      U     "ALLARMI_MP270".Allar_185;
      =     "Allarme 185";
NETWORK
TITLE =Mess.#186 Emergenza linea Comau da ripristinare

      U     "T2";
      =     L      0.0;
      U     L      0.0;
      UN    "Emerg. Comau ok";
      =     "ALLARMI_MP270".Allar_186;
      U     L      0.0;
      U     "ALLARMI_MP270".Allar_186;
      =     "Allarme 186";
NETWORK
TITLE =Mess.#187 Ripristinare sensore presenza su braccio AP&T

      U     "T2";
      =     L      0.0;
      U     L      0.0;
      U(    ;
      O     "M83.3";
      O     "M84.3";
      )     ;
      U     "M169.1";
      S     "ALLARMI_MP270".Allar_187;
      U     L      0.0;
      U(    ;
      ON    "M169.1";
      O     ;
      U     "AP&T in Manuale";
      U     "Merker Reset anom.";
      )     ;
      R     "ALLARMI_MP270".Allar_187;
      U     L      0.0;
      U     "ALLARMI_MP270".Allar_187;
      =     "Allarme 187";
NETWORK
TITLE =Mess.#189 AP&T non in start auto  (ciclo in corso)

      U     "T2";
      =     L      0.0;
      U     L      0.0;
      U     "AP&T in Automatico";
      U     "Cambio prod.: Passi a 0";
      UN    "AP&T  in ciclo";
      UN    "Allarme 64";
      UN    "Allarme 73";
      =     "ALLARMI_MP270".Allar_189;
      U     L      0.0;
      U     "ALLARMI_MP270".Allar_189;
      =     "Allarme 189";
NETWORK
TITLE =Allarme 190 Posizionare i gruppi a riposo per cambio tooling

      U     "T2";
      =     L      0.0;
      U     L      0.0;
      U     "Contr.gruppi a riposo";
      U(    ;
      ON    "Gruppi a riposo";
      ON    "Magneti Indietro";
      )     ;
      =     "ALLARMI_MP270".Allar_190;
      U     L      0.0;
      U(    ;
      O     "Gruppi a riposo";
      O     "Merker Reset anom.";
      )     ;
      U     "Magneti Indietro";
      R     "ALLARMI_MP270".Allar_190;
      U     L      0.0;
      U     "ALLARMI_MP270".Allar_190;
      =     "Allarme 190";
NETWORK
TITLE =Mess.#191 Retrofitting pulsanti EM non premuti per comau

      U     "T2";
      =     L      0.0;
      U     L      0.0;
      U(    ;
      U     "25K13";
      U     "25K14";
      U     "Retrofitt. Puls. EM";
      O     ;
      UN    "25K13";
      UN    "25K14";
      UN    "Retrofitt. Puls. EM";
      )     ;
      L     S5T#1S;
      SE    "T37";
      NOP   0;
      NOP   0;
      NOP   0;
      U     "T37";
      S     "ALLARMI_MP270".Allar_191;
      U     L      0.0;
      U     "ALLARMI_MP270".Allar_191;
      =     "Allarme 191";
NETWORK
TITLE =Mess.#192 Retrofitting Ripari chiusi per AP&T

      U     "T2";
      =     L      0.0;
      U     L      0.0;
      U(    ;
      U     "25K15";
      U     "25K16";
      U     "Retrofitt. Ripari x AP&T";
      O     ;
      UN    "25K15";
      UN    "25K16";
      UN    "Retrofitt. Ripari x AP&T";
      )     ;
      L     S5T#1S;
      SE    "T38";
      NOP   0;
      NOP   0;
      NOP   0;
      U     "T38";
      S     "ALLARMI_MP270".Allar_192;
      U     L      0.0;
      U     "ALLARMI_MP270".Allar_192;
      =     "Allarme 192";
NETWORK
TITLE =


NETWORK
TITLE =Segnalazioni da AP&T

      U     "ON";
      =     L      0.0;
      U(    ;
      U(    ;
      U(    ;
      U(    ;
      U     L      0.0;
      SPBNB _005;
      L     EW   500;
      T     DB2.DBW   30;
      SET   ;
      SAVE  ;
      CLR   ;
_005: U     BIE;
      )     ;
      SPBNB _006;
      L     EW   502;
      T     DB2.DBW   32;
      SET   ;
      SAVE  ;
      CLR   ;
_006: U     BIE;
      )     ;
      SPBNB _007;
      L     EW   504;
      T     DB2.DBW   34;
      SET   ;
      SAVE  ;
      CLR   ;
_007: U     BIE;
      )     ;
      SPBNB _008;
      L     EW   506;
      T     DB2.DBW   36;
      SET   ;
      SAVE  ;
      CLR   ;
_008: U     BIE;
      )     ;
      SPBNB _009;
      L     EW   508;
      T     DB2.DBW   38;
_009: NOP   0;
      U(    ;
      U(    ;
      U(    ;
      U(    ;
      U     L      0.0;
      SPBNB _00a;
      L     EW   510;
      T     DB2.DBW   40;
      SET   ;
      SAVE  ;
      CLR   ;
_00a: U     BIE;
      )     ;
      SPBNB _00b;
      L     EW   512;
      T     DB2.DBW   42;
      SET   ;
      SAVE  ;
      CLR   ;
_00b: U     BIE;
      )     ;
      SPBNB _00c;
      L     EW   514;
      T     DB2.DBW   44;
      SET   ;
      SAVE  ;
      CLR   ;
_00c: U     BIE;
      )     ;
      SPBNB _00d;
      L     EW   516;
      T     DB2.DBW   46;
      SET   ;
      SAVE  ;
      CLR   ;
_00d: U     BIE;
      )     ;
      SPBNB _00e;
      L     EW   518;
      T     DB2.DBW   48;
_00e: NOP   0;
NETWORK
TITLE =Allarmi presenti

      O(    ;
      L     DB2.DBD    0;
      L     L#0;
      >D    ;
      )     ;
      O(    ;
      L     DB2.DBD    4;
      L     L#0;
      >D    ;
      )     ;
      O(    ;
      L     DB2.DBD    8;
      L     L#0;
      >D    ;
      )     ;
      O(    ;
      L     DB2.DBD   12;
      L     L#0;
      >D    ;
      )     ;
      O(    ;
      L     DB2.DBD   16;
      L     L#0;
      >D    ;
      )     ;
      O(    ;
      L     DB2.DBD   20;
      L     L#0;
      >D    ;
      )     ;
      =     "M7.0";
NETWORK
TITLE =PreAllarmi presenti

      U     "T2";
      U     "26SA1";
      UN    "Allarme 1";
      =     "ALLARMI_MP270".Allar_41;
      =     "Allarme 41";
END_FUNCTION_BLOCK

